VERSION 5.8 ;
BUSBITCHARS "[]" ;
DIVIDERCHAR "/" ;
 
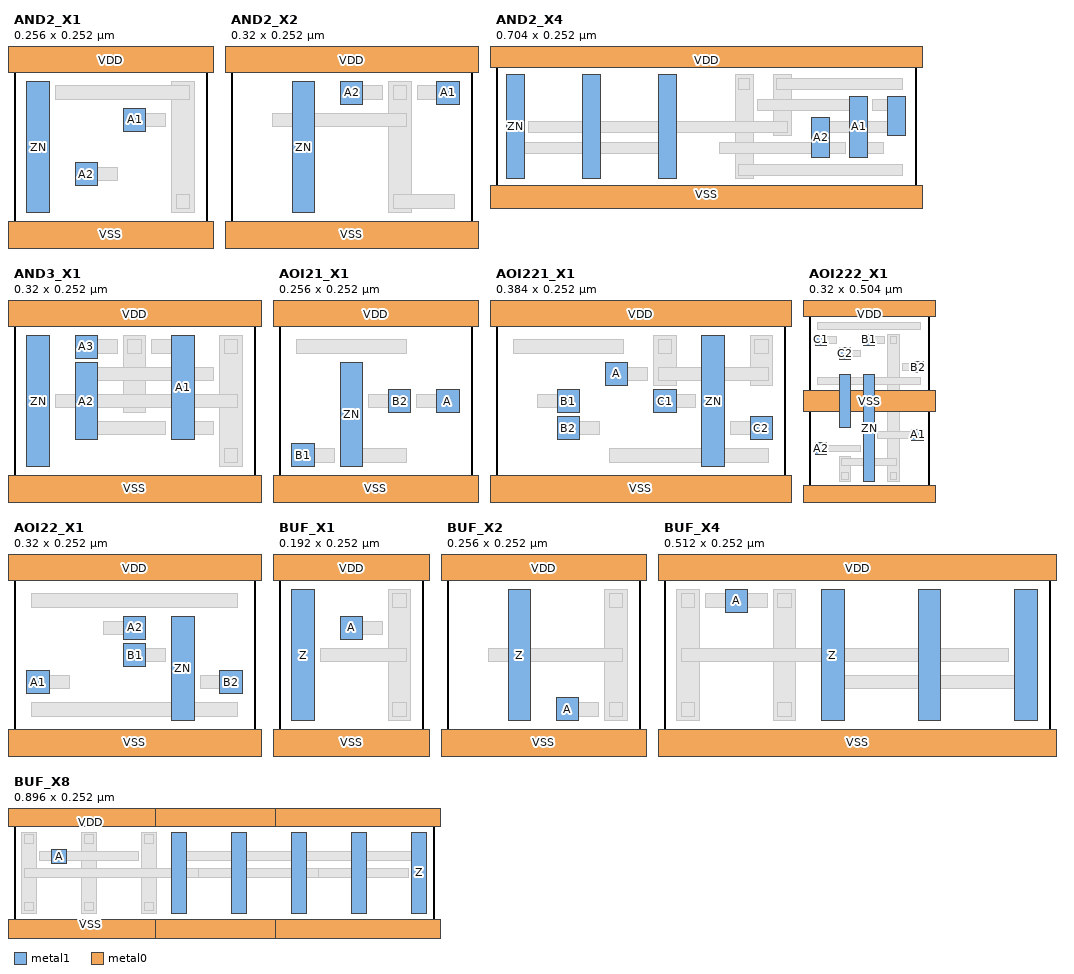
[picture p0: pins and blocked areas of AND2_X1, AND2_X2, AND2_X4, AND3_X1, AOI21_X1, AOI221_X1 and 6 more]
MACRO AND2_X1
  CLASS CORE ;
  FOREIGN AND2_X1 0 0 ;
  SIZE 0.256 BY 0.252 ;
  ORIGIN 0.0 0.0 ;
  SYMMETRY X Y ;
  PIN A1
    DIRECTION INPUT ;
    USE SIGNAL ;
    ANTENNAGATEAREA 0.001656 ;
    PORT
      LAYER metal1 ;
        RECT 0.145 0.147 0.175 0.177 ;
    END
  END A1
  PIN A2
    DIRECTION INPUT ;
    USE SIGNAL ;
    ANTENNAGATEAREA 0.001656 ;
    PORT
      LAYER metal1 ;
        RECT 0.081 0.075 0.111 0.105 ;
    END
  END A2
  PIN ZN
    DIRECTION OUTPUT ;
    USE SIGNAL ;
    ANTENNADIFFAREA 0.004232 ;
    PORT
      LAYER metal1 ;
        RECT 0.017 0.039 0.047 0.213 ;
    END
  END ZN
  PIN VDD
    DIRECTION INOUT ;
    USE POWER ;
    PORT
      LAYER metal0 ;
        RECT -0.019 0.225 0.275 0.279 ;
    END
  END VDD
  PIN VSS
    DIRECTION INOUT ;
    USE GROUND ;
    PORT
      LAYER metal0 ;
        RECT -0.019 -0.027 0.275 0.027 ;
    END
  END VSS
  OBS
    LAYER metal1 ;
      RECT 0.209 0.039 0.239 0.213 ;
    LAYER metal0 ;
      RECT 0.055 0.189 0.233 0.207 ;
      RECT 0.215 0.045 0.233 0.063 ;
      RECT 0.151 0.153 0.201 0.171 ;
      RECT 0.087 0.081 0.137 0.099 ;
      RECT 0.023 0.189 0.041 0.207 ;
      RECT 0.023 0.045 0.041 0.063 ;
  END
END AND2_X1

MACRO AND2_X2
  CLASS CORE ;
  FOREIGN AND2_X2 0 0 ;
  SIZE 0.32 BY 0.252 ;
  ORIGIN 0.0 0.0 ;
  SYMMETRY X Y ;
  PIN A1
    DIRECTION INPUT ;
    USE SIGNAL ;
    ANTENNAGATEAREA 0.001656 ;
    PORT
      LAYER metal1 ;
        RECT 0.273 0.183 0.303 0.213 ;
    END
  END A1
  PIN A2
    DIRECTION INPUT ;
    USE SIGNAL ;
    ANTENNAGATEAREA 0.001656 ;
    PORT
      LAYER metal1 ;
        RECT 0.145 0.183 0.175 0.213 ;
    END
  END A2
  PIN ZN
    DIRECTION OUTPUT ;
    USE SIGNAL ;
    ANTENNADIFFAREA 0.004232 ;
    PORT
      LAYER metal1 ;
        RECT 0.081 0.039 0.111 0.213 ;
    END
  END ZN
  PIN VDD
    DIRECTION INOUT ;
    USE POWER ;
    PORT
      LAYER metal0 ;
        RECT -0.019 0.225 0.339 0.279 ;
    END
  END VDD
  PIN VSS
    DIRECTION INOUT ;
    USE GROUND ;
    PORT
      LAYER metal0 ;
        RECT -0.019 -0.027 0.339 0.027 ;
    END
  END VSS
  OBS
    LAYER metal1 ;
      RECT 0.209 0.039 0.239 0.213 ;
    LAYER metal0 ;
      RECT 0.055 0.153 0.233 0.171 ;
      RECT 0.215 0.045 0.297 0.063 ;
      RECT 0.215 0.189 0.233 0.207 ;
      RECT 0.247 0.189 0.297 0.207 ;
      RECT 0.151 0.189 0.201 0.207 ;
      RECT 0.087 0.189 0.105 0.207 ;
      RECT 0.087 0.045 0.105 0.063 ;
  END
END AND2_X2

MACRO AND2_X4
  CLASS CORE ;
  FOREIGN AND2_X4 0 0 ;
  SIZE 0.704 BY 0.252 ;
  ORIGIN 0.0 0.0 ;
  SYMMETRY X Y ;
  PIN A1
    DIRECTION INPUT ;
    USE SIGNAL ;
    ANTENNAGATEAREA 0.003312 ;
    PORT
      LAYER metal1 ;
        RECT 0.593 0.075 0.623 0.177 ;
    END
  END A1
  PIN A2
    DIRECTION INPUT ;
    USE SIGNAL ;
    ANTENNAGATEAREA 0.003312 ;
    PORT
      LAYER metal1 ;
        RECT 0.529 0.075 0.559 0.141 ;
        RECT 0.657 0.111 0.687 0.177 ;
    END
  END A2
  PIN ZN
    DIRECTION OUTPUT ;
    USE SIGNAL ;
    ANTENNADIFFAREA 0.012696 ;
    PORT
      LAYER metal1 ;
        RECT 0.017 0.039 0.047 0.213 ;
        RECT 0.145 0.039 0.175 0.213 ;
        RECT 0.273 0.039 0.303 0.213 ;
    END
  END ZN
  PIN VDD
    DIRECTION INOUT ;
    USE POWER ;
    PORT
      LAYER metal0 ;
        RECT -0.019 0.225 0.723 0.279 ;
    END
  END VDD
  PIN VSS
    DIRECTION INOUT ;
    USE GROUND ;
    PORT
      LAYER metal0 ;
        RECT -0.019 -0.027 0.723 0.027 ;
    END
  END VSS
  OBS
    LAYER metal1 ;
      RECT 0.401 0.039 0.431 0.213 ;
      RECT 0.465 0.111 0.495 0.213 ;
    LAYER metal0 ;
      RECT 0.471 0.189 0.681 0.207 ;
      RECT 0.055 0.117 0.489 0.135 ;
      RECT 0.407 0.045 0.681 0.063 ;
      RECT 0.407 0.189 0.425 0.207 ;
      RECT 0.439 0.153 0.617 0.171 ;
      RECT 0.599 0.081 0.649 0.099 ;
      RECT 0.535 0.117 0.681 0.135 ;
      RECT 0.375 0.081 0.585 0.099 ;
      RECT 0.631 0.153 0.681 0.171 ;
      RECT 0.023 0.081 0.297 0.099 ;
      RECT 0.023 0.189 0.041 0.207 ;
      RECT 0.023 0.045 0.041 0.063 ;
      RECT 0.279 0.045 0.297 0.063 ;
      RECT 0.279 0.189 0.297 0.207 ;
      RECT 0.151 0.189 0.169 0.207 ;
      RECT 0.151 0.045 0.169 0.063 ;
  END
END AND2_X4

MACRO AND3_X1
  CLASS CORE ;
  FOREIGN AND3_X1 0 0 ;
  SIZE 0.32 BY 0.252 ;
  ORIGIN 0.0 0.0 ;
  SYMMETRY X Y ;
  PIN A1
    DIRECTION INPUT ;
    USE SIGNAL ;
    ANTENNAGATEAREA 0.001656 ;
    PORT
      LAYER metal1 ;
        RECT 0.209 0.075 0.239 0.213 ;
    END
  END A1
  PIN A2
    DIRECTION INPUT ;
    USE SIGNAL ;
    ANTENNAGATEAREA 0.001656 ;
    PORT
      LAYER metal1 ;
        RECT 0.081 0.075 0.111 0.177 ;
    END
  END A2
  PIN A3
    DIRECTION INPUT ;
    USE SIGNAL ;
    ANTENNAGATEAREA 0.001656 ;
    PORT
      LAYER metal1 ;
        RECT 0.081 0.183 0.111 0.213 ;
    END
  END A3
  PIN ZN
    DIRECTION OUTPUT ;
    USE SIGNAL ;
    ANTENNADIFFAREA 0.004232 ;
    PORT
      LAYER metal1 ;
        RECT 0.017 0.039 0.047 0.213 ;
    END
  END ZN
  PIN VDD
    DIRECTION INOUT ;
    USE POWER ;
    PORT
      LAYER metal0 ;
        RECT -0.019 0.225 0.339 0.279 ;
    END
  END VDD
  PIN VSS
    DIRECTION INOUT ;
    USE GROUND ;
    PORT
      LAYER metal0 ;
        RECT -0.019 -0.027 0.339 0.027 ;
    END
  END VSS
  OBS
    LAYER metal1 ;
      RECT 0.145 0.111 0.175 0.213 ;
      RECT 0.273 0.039 0.303 0.213 ;
    LAYER metal0 ;
      RECT 0.055 0.117 0.297 0.135 ;
      RECT 0.151 0.189 0.169 0.207 ;
      RECT 0.279 0.189 0.297 0.207 ;
      RECT 0.279 0.045 0.297 0.063 ;
      RECT 0.215 0.081 0.265 0.099 ;
      RECT 0.183 0.189 0.233 0.207 ;
      RECT 0.087 0.153 0.265 0.171 ;
      RECT 0.087 0.081 0.201 0.099 ;
      RECT 0.087 0.189 0.137 0.207 ;
      RECT 0.023 0.189 0.041 0.207 ;
      RECT 0.023 0.045 0.041 0.063 ;
  END
END AND3_X1

MACRO AOI21_X1
  CLASS CORE ;
  FOREIGN AOI21_X1 0 0 ;
  SIZE 0.256 BY 0.252 ;
  ORIGIN 0.0 0.0 ;
  SYMMETRY X Y ;
  PIN A
    DIRECTION INPUT ;
    USE SIGNAL ;
    ANTENNAGATEAREA 0.001656 ;
    PORT
      LAYER metal1 ;
        RECT 0.209 0.111 0.239 0.141 ;
    END
  END A
  PIN B1
    DIRECTION INPUT ;
    USE SIGNAL ;
    ANTENNAGATEAREA 0.001656 ;
    PORT
      LAYER metal1 ;
        RECT 0.017 0.039 0.047 0.069 ;
    END
  END B1
  PIN B2
    DIRECTION INPUT ;
    USE SIGNAL ;
    ANTENNAGATEAREA 0.001656 ;
    PORT
      LAYER metal1 ;
        RECT 0.145 0.111 0.175 0.141 ;
    END
  END B2
  PIN ZN
    DIRECTION OUTPUT ;
    USE SIGNAL ;
    ANTENNADIFFAREA 0.004232 ;
    PORT
      LAYER metal1 ;
        RECT 0.081 0.039 0.111 0.177 ;
    END
  END ZN
  PIN VDD
    DIRECTION INOUT ;
    USE POWER ;
    PORT
      LAYER metal0 ;
        RECT -0.019 0.225 0.275 0.279 ;
    END
  END VDD
  PIN VSS
    DIRECTION INOUT ;
    USE GROUND ;
    PORT
      LAYER metal0 ;
        RECT -0.019 -0.027 0.275 0.027 ;
    END
  END VSS
  OBS
    LAYER metal0 ;
      RECT 0.023 0.189 0.169 0.207 ;
      RECT 0.183 0.117 0.233 0.135 ;
      RECT 0.023 0.045 0.073 0.063 ;
      RECT 0.119 0.117 0.169 0.135 ;
      RECT 0.087 0.045 0.169 0.063 ;
      RECT 0.087 0.153 0.105 0.171 ;
  END
END AOI21_X1

MACRO AOI221_X1
  CLASS CORE ;
  FOREIGN AOI221_X1 0 0 ;
  SIZE 0.384 BY 0.252 ;
  ORIGIN 0.0 0.0 ;
  SYMMETRY X Y ;
  PIN A
    DIRECTION INPUT ;
    USE SIGNAL ;
    ANTENNAGATEAREA 0.001656 ;
    PORT
      LAYER metal1 ;
        RECT 0.145 0.147 0.175 0.177 ;
    END
  END A
  PIN B1
    DIRECTION INPUT ;
    USE SIGNAL ;
    ANTENNAGATEAREA 0.001656 ;
    PORT
      LAYER metal1 ;
        RECT 0.081 0.111 0.111 0.141 ;
    END
  END B1
  PIN B2
    DIRECTION INPUT ;
    USE SIGNAL ;
    ANTENNAGATEAREA 0.001656 ;
    PORT
      LAYER metal1 ;
        RECT 0.081 0.075 0.111 0.105 ;
    END
  END B2
  PIN C1
    DIRECTION INPUT ;
    USE SIGNAL ;
    ANTENNAGATEAREA 0.001656 ;
    PORT
      LAYER metal1 ;
        RECT 0.209 0.111 0.239 0.141 ;
    END
  END C1
  PIN C2
    DIRECTION INPUT ;
    USE SIGNAL ;
    ANTENNAGATEAREA 0.001656 ;
    PORT
      LAYER metal1 ;
        RECT 0.337 0.075 0.367 0.105 ;
    END
  END C2
  PIN ZN
    DIRECTION OUTPUT ;
    USE SIGNAL ;
    ANTENNADIFFAREA 0.006348 ;
    PORT
      LAYER metal1 ;
        RECT 0.273 0.039 0.303 0.213 ;
    END
  END ZN
  PIN VDD
    DIRECTION INOUT ;
    USE POWER ;
    PORT
      LAYER metal0 ;
        RECT -0.019 0.225 0.403 0.279 ;
    END
  END VDD
  PIN VSS
    DIRECTION INOUT ;
    USE GROUND ;
    PORT
      LAYER metal0 ;
        RECT -0.019 -0.027 0.403 0.027 ;
    END
  END VSS
  OBS
    LAYER metal1 ;
      RECT 0.209 0.147 0.239 0.213 ;
      RECT 0.337 0.147 0.367 0.213 ;
    LAYER metal0 ;
      RECT 0.023 0.189 0.169 0.207 ;
      RECT 0.215 0.153 0.361 0.171 ;
      RECT 0.215 0.189 0.233 0.207 ;
      RECT 0.343 0.189 0.361 0.207 ;
      RECT 0.151 0.153 0.201 0.171 ;
      RECT 0.055 0.117 0.105 0.135 ;
      RECT 0.087 0.081 0.137 0.099 ;
      RECT 0.215 0.117 0.265 0.135 ;
      RECT 0.311 0.081 0.361 0.099 ;
      RECT 0.279 0.189 0.297 0.207 ;
      RECT 0.151 0.045 0.361 0.063 ;
  END
END AOI221_X1

MACRO AOI222_X1
  CLASS CORE ;
  FOREIGN AOI222_X1 0 0 ;
  SIZE 0.32 BY 0.504 ;
  ORIGIN 0.0 0.0 ;
  SYMMETRY X Y ;
  PIN A1
    DIRECTION INPUT ;
    USE SIGNAL ;
    ANTENNAGATEAREA 0.001656 ;
    PORT
      LAYER metal1 ;
        RECT 0.273 0.147 0.303 0.177 ;
    END
  END A1
  PIN A2
    DIRECTION INPUT ;
    USE SIGNAL ;
    ANTENNAGATEAREA 0.001656 ;
    PORT
      LAYER metal1 ;
        RECT 0.017 0.111 0.047 0.141 ;
    END
  END A2
  PIN B1
    DIRECTION INPUT ;
    USE SIGNAL ;
    ANTENNAGATEAREA 0.001656 ;
    PORT
      LAYER metal1 ;
        RECT 0.145 0.399 0.175 0.429 ;
    END
  END B1
  PIN B2
    DIRECTION INPUT ;
    USE SIGNAL ;
    ANTENNAGATEAREA 0.001656 ;
    PORT
      LAYER metal1 ;
        RECT 0.273 0.327 0.303 0.357 ;
    END
  END B2
  PIN C1
    DIRECTION INPUT ;
    USE SIGNAL ;
    ANTENNAGATEAREA 0.001656 ;
    PORT
      LAYER metal1 ;
        RECT 0.017 0.399 0.047 0.429 ;
    END
  END C1
  PIN C2
    DIRECTION INPUT ;
    USE SIGNAL ;
    ANTENNAGATEAREA 0.001656 ;
    PORT
      LAYER metal1 ;
        RECT 0.081 0.363 0.111 0.393 ;
    END
  END C2
  PIN ZN
    DIRECTION OUTPUT ;
    USE SIGNAL ;
    ANTENNADIFFAREA 0.008464 ;
    PORT
      LAYER metal1 ;
        RECT 0.081 0.183 0.111 0.321 ;
        RECT 0.145 0.039 0.175 0.321 ;
    END
  END ZN
  PIN VDD
    DIRECTION INOUT ;
    USE POWER ;
    PORT
      LAYER metal0 ;
        RECT -0.019 -0.027 0.339 0.027 ;
        RECT -0.019 0.477 0.339 0.531 ;
    END
  END VDD
  PIN VSS
    DIRECTION INOUT ;
    USE GROUND ;
    PORT
      LAYER metal0 ;
        RECT -0.019 0.225 0.339 0.279 ;
    END
  END VSS
  OBS
    LAYER metal1 ;
      RECT 0.209 0.039 0.239 0.429 ;
      RECT 0.081 0.039 0.111 0.105 ;
    LAYER metal0 ;
      RECT 0.215 0.045 0.233 0.063 ;
      RECT 0.087 0.045 0.105 0.063 ;
      RECT 0.215 0.405 0.233 0.423 ;
      RECT 0.087 0.081 0.233 0.099 ;
      RECT 0.023 0.441 0.297 0.459 ;
      RECT 0.183 0.153 0.297 0.171 ;
      RECT 0.023 0.117 0.137 0.135 ;
      RECT 0.151 0.405 0.201 0.423 ;
      RECT 0.247 0.333 0.297 0.351 ;
      RECT 0.023 0.405 0.073 0.423 ;
      RECT 0.087 0.369 0.137 0.387 ;
      RECT 0.087 0.189 0.105 0.207 ;
      RECT 0.023 0.297 0.297 0.315 ;
      RECT 0.151 0.045 0.169 0.063 ;
  END
END AOI222_X1

MACRO AOI22_X1
  CLASS CORE ;
  FOREIGN AOI22_X1 0 0 ;
  SIZE 0.32 BY 0.252 ;
  ORIGIN 0.0 0.0 ;
  SYMMETRY X Y ;
  PIN A1
    DIRECTION INPUT ;
    USE SIGNAL ;
    ANTENNAGATEAREA 0.001656 ;
    PORT
      LAYER metal1 ;
        RECT 0.017 0.075 0.047 0.105 ;
    END
  END A1
  PIN A2
    DIRECTION INPUT ;
    USE SIGNAL ;
    ANTENNAGATEAREA 0.001656 ;
    PORT
      LAYER metal1 ;
        RECT 0.145 0.147 0.175 0.177 ;
    END
  END A2
  PIN B1
    DIRECTION INPUT ;
    USE SIGNAL ;
    ANTENNAGATEAREA 0.001656 ;
    PORT
      LAYER metal1 ;
        RECT 0.145 0.111 0.175 0.141 ;
    END
  END B1
  PIN B2
    DIRECTION INPUT ;
    USE SIGNAL ;
    ANTENNAGATEAREA 0.001656 ;
    PORT
      LAYER metal1 ;
        RECT 0.273 0.075 0.303 0.105 ;
    END
  END B2
  PIN ZN
    DIRECTION OUTPUT ;
    USE SIGNAL ;
    ANTENNADIFFAREA 0.006348 ;
    PORT
      LAYER metal1 ;
        RECT 0.209 0.039 0.239 0.177 ;
    END
  END ZN
  PIN VDD
    DIRECTION INOUT ;
    USE POWER ;
    PORT
      LAYER metal0 ;
        RECT -0.019 0.225 0.339 0.279 ;
    END
  END VDD
  PIN VSS
    DIRECTION INOUT ;
    USE GROUND ;
    PORT
      LAYER metal0 ;
        RECT -0.019 -0.027 0.339 0.027 ;
    END
  END VSS
  OBS
    LAYER metal0 ;
      RECT 0.023 0.189 0.297 0.207 ;
      RECT 0.023 0.081 0.073 0.099 ;
      RECT 0.119 0.153 0.169 0.171 ;
      RECT 0.151 0.117 0.201 0.135 ;
      RECT 0.247 0.081 0.297 0.099 ;
      RECT 0.215 0.153 0.233 0.171 ;
      RECT 0.023 0.045 0.297 0.063 ;
  END
END AOI22_X1

MACRO BUF_X1
  CLASS CORE ;
  FOREIGN BUF_X1 0 0 ;
  SIZE 0.192 BY 0.252 ;
  ORIGIN 0.0 0.0 ;
  SYMMETRY X Y ;
  PIN A
    DIRECTION INPUT ;
    USE SIGNAL ;
    ANTENNAGATEAREA 0.001656 ;
    PORT
      LAYER metal1 ;
        RECT 0.081 0.147 0.111 0.177 ;
    END
  END A
  PIN Z
    DIRECTION OUTPUT ;
    USE SIGNAL ;
    ANTENNADIFFAREA 0.004232 ;
    PORT
      LAYER metal1 ;
        RECT 0.017 0.039 0.047 0.213 ;
    END
  END Z
  PIN VDD
    DIRECTION INOUT ;
    USE POWER ;
    PORT
      LAYER metal0 ;
        RECT -0.019 0.225 0.211 0.279 ;
    END
  END VDD
  PIN VSS
    DIRECTION INOUT ;
    USE GROUND ;
    PORT
      LAYER metal0 ;
        RECT -0.019 -0.027 0.211 0.027 ;
    END
  END VSS
  OBS
    LAYER metal1 ;
      RECT 0.145 0.039 0.175 0.213 ;
    LAYER metal0 ;
      RECT 0.055 0.117 0.169 0.135 ;
      RECT 0.151 0.189 0.169 0.207 ;
      RECT 0.151 0.045 0.169 0.063 ;
      RECT 0.087 0.153 0.137 0.171 ;
      RECT 0.023 0.189 0.041 0.207 ;
      RECT 0.023 0.045 0.041 0.063 ;
  END
END BUF_X1

MACRO BUF_X2
  CLASS CORE ;
  FOREIGN BUF_X2 0 0 ;
  SIZE 0.256 BY 0.252 ;
  ORIGIN 0.0 0.0 ;
  SYMMETRY X Y ;
  PIN A
    DIRECTION INPUT ;
    USE SIGNAL ;
    ANTENNAGATEAREA 0.001656 ;
    PORT
      LAYER metal1 ;
        RECT 0.145 0.039 0.175 0.069 ;
    END
  END A
  PIN Z
    DIRECTION OUTPUT ;
    USE SIGNAL ;
    ANTENNADIFFAREA 0.004232 ;
    PORT
      LAYER metal1 ;
        RECT 0.081 0.039 0.111 0.213 ;
    END
  END Z
  PIN VDD
    DIRECTION INOUT ;
    USE POWER ;
    PORT
      LAYER metal0 ;
        RECT -0.019 0.225 0.275 0.279 ;
    END
  END VDD
  PIN VSS
    DIRECTION INOUT ;
    USE GROUND ;
    PORT
      LAYER metal0 ;
        RECT -0.019 -0.027 0.275 0.027 ;
    END
  END VSS
  OBS
    LAYER metal1 ;
      RECT 0.209 0.039 0.239 0.213 ;
    LAYER metal0 ;
      RECT 0.055 0.117 0.233 0.135 ;
      RECT 0.215 0.189 0.233 0.207 ;
      RECT 0.215 0.045 0.233 0.063 ;
      RECT 0.151 0.045 0.201 0.063 ;
      RECT 0.087 0.189 0.105 0.207 ;
      RECT 0.087 0.045 0.105 0.063 ;
  END
END BUF_X2

MACRO BUF_X4
  CLASS CORE ;
  FOREIGN BUF_X4 0 0 ;
  SIZE 0.512 BY 0.252 ;
  ORIGIN 0.0 0.0 ;
  SYMMETRY X Y ;
  PIN A
    DIRECTION INPUT ;
    USE SIGNAL ;
    ANTENNAGATEAREA 0.003312 ;
    PORT
      LAYER metal1 ;
        RECT 0.081 0.183 0.111 0.213 ;
    END
  END A
  PIN Z
    DIRECTION OUTPUT ;
    USE SIGNAL ;
    ANTENNADIFFAREA 0.012696 ;
    PORT
      LAYER metal1 ;
        RECT 0.209 0.039 0.239 0.213 ;
        RECT 0.465 0.039 0.495 0.213 ;
        RECT 0.337 0.039 0.367 0.213 ;
    END
  END Z
  PIN VDD
    DIRECTION INOUT ;
    USE POWER ;
    PORT
      LAYER metal0 ;
        RECT -0.019 0.225 0.531 0.279 ;
    END
  END VDD
  PIN VSS
    DIRECTION INOUT ;
    USE GROUND ;
    PORT
      LAYER metal0 ;
        RECT -0.019 -0.027 0.531 0.027 ;
    END
  END VSS
  OBS
    LAYER metal1 ;
      RECT 0.017 0.039 0.047 0.213 ;
      RECT 0.145 0.039 0.175 0.213 ;
    LAYER metal0 ;
      RECT 0.023 0.117 0.457 0.135 ;
      RECT 0.023 0.189 0.041 0.207 ;
      RECT 0.151 0.189 0.169 0.207 ;
      RECT 0.023 0.045 0.041 0.063 ;
      RECT 0.151 0.045 0.169 0.063 ;
      RECT 0.055 0.189 0.137 0.207 ;
      RECT 0.215 0.045 0.233 0.063 ;
      RECT 0.215 0.189 0.233 0.207 ;
      RECT 0.215 0.081 0.489 0.099 ;
      RECT 0.343 0.045 0.361 0.063 ;
      RECT 0.343 0.189 0.361 0.207 ;
      RECT 0.471 0.045 0.489 0.063 ;
      RECT 0.471 0.189 0.489 0.207 ;
  END
END BUF_X4

MACRO BUF_X8
  CLASS CORE ;
  FOREIGN BUF_X8 0 0 ;
  SIZE 0.896 BY 0.252 ;
  ORIGIN 0.0 0.0 ;
  SYMMETRY X Y ;
  PIN A
    DIRECTION INPUT ;
    USE SIGNAL ;
    ANTENNAGATEAREA 0.006624 ;
    PORT
      LAYER metal1 ;
        RECT 0.081 0.147 0.111 0.177 ;
    END
  END A
  PIN Z
    DIRECTION OUTPUT ;
    USE SIGNAL ;
    ANTENNADIFFAREA 0.021160 ;
    PORT
      LAYER metal1 ;
        RECT 0.849 0.039 0.879 0.213 ;
        RECT 0.465 0.039 0.495 0.213 ;
        RECT 0.721 0.039 0.751 0.213 ;
        RECT 0.337 0.039 0.367 0.213 ;
        RECT 0.593 0.039 0.623 0.213 ;
    END
  END Z
  PIN VDD
    DIRECTION INOUT ;
    USE POWER ;
    PORT
      LAYER metal0 ;
        RECT -0.019 0.225 0.339 0.279 ;
        RECT 0.301 0.225 0.659 0.279 ;
        RECT 0.557 0.225 0.915 0.279 ;
    END
  END VDD
  PIN VSS
    DIRECTION INOUT ;
    USE GROUND ;
    PORT
      LAYER metal0 ;
        RECT 0.557 -0.027 0.915 0.027 ;
        RECT -0.019 -0.027 0.339 0.027 ;
        RECT 0.301 -0.027 0.659 0.027 ;
    END
  END VSS
  OBS
    LAYER metal1 ;
      RECT 0.273 0.039 0.303 0.213 ;
      RECT 0.145 0.039 0.175 0.213 ;
      RECT 0.017 0.039 0.047 0.213 ;
    LAYER metal0 ;
      RECT 0.631 0.117 0.841 0.135 ;
      RECT 0.375 0.117 0.649 0.135 ;
      RECT 0.279 0.045 0.297 0.063 ;
      RECT 0.151 0.045 0.169 0.063 ;
      RECT 0.023 0.045 0.041 0.063 ;
      RECT 0.279 0.189 0.297 0.207 ;
      RECT 0.151 0.189 0.169 0.207 ;
      RECT 0.023 0.189 0.041 0.207 ;
      RECT 0.023 0.117 0.393 0.135 ;
      RECT 0.055 0.153 0.265 0.171 ;
      RECT 0.855 0.189 0.873 0.207 ;
      RECT 0.599 0.153 0.873 0.171 ;
      RECT 0.343 0.153 0.617 0.171 ;
      RECT 0.855 0.045 0.873 0.063 ;
      RECT 0.343 0.045 0.361 0.063 ;
      RECT 0.471 0.045 0.489 0.063 ;
      RECT 0.471 0.189 0.489 0.207 ;
      RECT 0.599 0.045 0.617 0.063 ;
      RECT 0.727 0.045 0.745 0.063 ;
      RECT 0.727 0.189 0.745 0.207 ;
      RECT 0.343 0.189 0.361 0.207 ;
      RECT 0.599 0.189 0.617 0.207 ;
  END
END BUF_X8

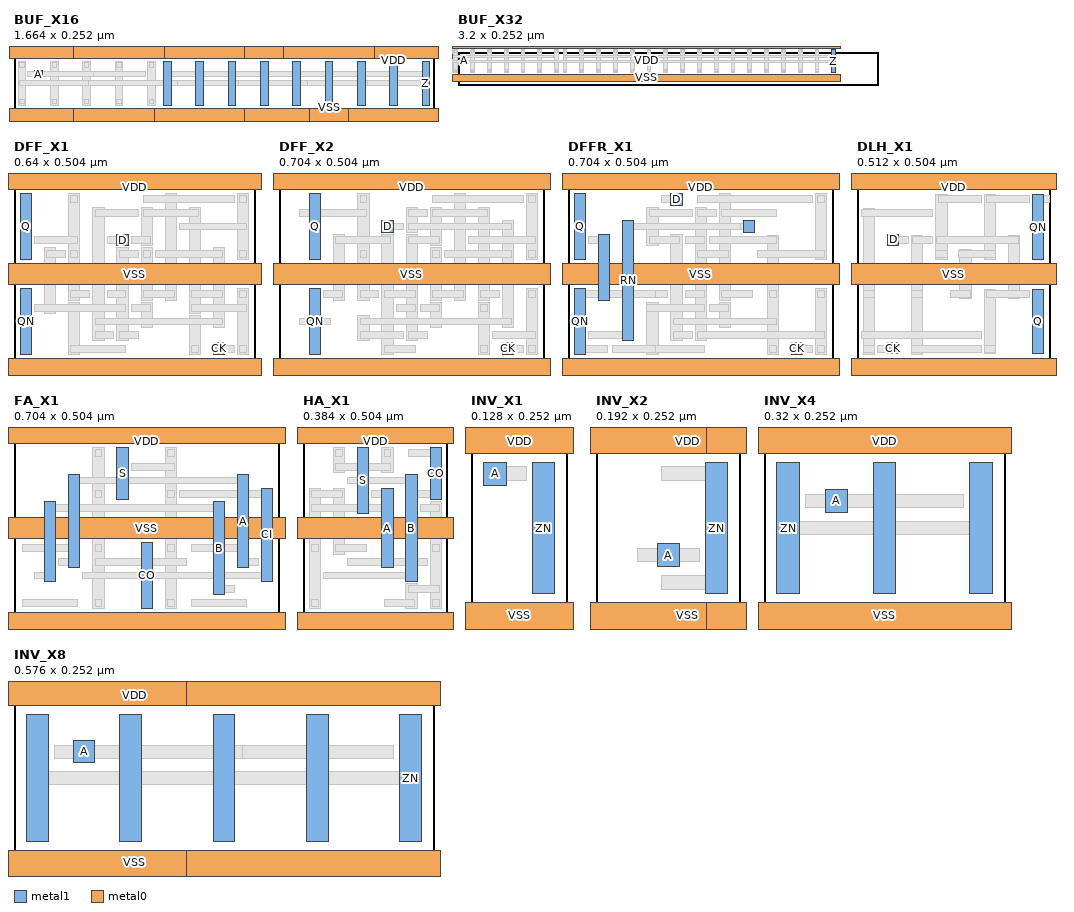
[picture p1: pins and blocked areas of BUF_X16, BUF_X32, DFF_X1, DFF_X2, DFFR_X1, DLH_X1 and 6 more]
MACRO BUF_X16
  CLASS CORE ;
  FOREIGN BUF_X16 0 0 ;
  SIZE 1.664 BY 0.252 ;
  ORIGIN 0.0 0.0 ;
  SYMMETRY X Y ;
  PIN A
    DIRECTION INPUT ;
    USE SIGNAL ;
    ANTENNAGATEAREA 0.013248 ;
    PORT
      LAYER metal1 ;
        RECT 0.081 0.147 0.111 0.177 ;
    END
  END A
  PIN Z
    DIRECTION OUTPUT ;
    USE SIGNAL ;
    ANTENNADIFFAREA 0.038088 ;
    PORT
      LAYER metal1 ;
        RECT 1.617 0.039 1.647 0.213 ;
        RECT 1.233 0.039 1.263 0.213 ;
        RECT 0.721 0.039 0.751 0.213 ;
        RECT 0.849 0.039 0.879 0.213 ;
        RECT 1.489 0.039 1.519 0.213 ;
        RECT 1.361 0.039 1.391 0.213 ;
        RECT 0.593 0.039 0.623 0.213 ;
        RECT 1.105 0.039 1.135 0.213 ;
        RECT 0.977 0.039 1.007 0.213 ;
    END
  END Z
  PIN VDD
    DIRECTION INOUT ;
    USE POWER ;
    PORT
      LAYER metal0 ;
        RECT -0.019 0.225 0.339 0.279 ;
        RECT 0.557 0.225 0.915 0.279 ;
        RECT 1.325 0.225 1.683 0.279 ;
        RECT 0.813 0.225 1.171 0.279 ;
        RECT 0.237 0.225 0.595 0.279 ;
        RECT 1.069 0.225 1.427 0.279 ;
    END
  END VDD
  PIN VSS
    DIRECTION INOUT ;
    USE GROUND ;
    PORT
      LAYER metal0 ;
        RECT 1.069 -0.027 1.427 0.027 ;
        RECT 0.813 -0.027 1.171 0.027 ;
        RECT 0.237 -0.027 0.595 0.027 ;
        RECT 0.557 -0.027 0.915 0.027 ;
        RECT -0.019 -0.027 0.339 0.027 ;
        RECT 1.325 -0.027 1.683 0.027 ;
    END
  END VSS
  OBS
    LAYER metal1 ;
      RECT 0.529 0.039 0.559 0.213 ;
      RECT 0.401 0.039 0.431 0.213 ;
      RECT 0.273 0.039 0.303 0.213 ;
      RECT 0.145 0.039 0.175 0.213 ;
      RECT 0.017 0.039 0.047 0.213 ;
    LAYER metal0 ;
      RECT 1.143 0.117 1.401 0.135 ;
      RECT 1.399 0.117 1.609 0.135 ;
      RECT 0.887 0.117 1.161 0.135 ;
      RECT 0.631 0.117 0.889 0.135 ;
      RECT 0.535 0.045 0.553 0.063 ;
      RECT 0.407 0.045 0.425 0.063 ;
      RECT 0.279 0.045 0.297 0.063 ;
      RECT 0.535 0.189 0.553 0.207 ;
      RECT 0.407 0.189 0.425 0.207 ;
      RECT 0.279 0.189 0.297 0.207 ;
      RECT 0.279 0.117 0.649 0.135 ;
      RECT 0.151 0.045 0.169 0.063 ;
      RECT 0.023 0.045 0.041 0.063 ;
      RECT 0.151 0.189 0.169 0.207 ;
      RECT 0.023 0.189 0.041 0.207 ;
      RECT 0.023 0.117 0.297 0.135 ;
      RECT 0.311 0.153 0.521 0.171 ;
      RECT 0.055 0.153 0.313 0.171 ;
      RECT 0.599 0.153 0.873 0.171 ;
      RECT 1.367 0.153 1.641 0.171 ;
      RECT 1.623 0.189 1.641 0.207 ;
      RECT 1.111 0.153 1.385 0.171 ;
      RECT 0.855 0.153 1.129 0.171 ;
      RECT 1.623 0.045 1.641 0.063 ;
      RECT 1.367 0.045 1.385 0.063 ;
      RECT 1.239 0.189 1.257 0.207 ;
      RECT 0.599 0.045 0.617 0.063 ;
      RECT 1.367 0.189 1.385 0.207 ;
      RECT 0.983 0.045 1.001 0.063 ;
      RECT 1.495 0.045 1.513 0.063 ;
      RECT 0.983 0.189 1.001 0.207 ;
      RECT 0.727 0.045 0.745 0.063 ;
      RECT 1.111 0.189 1.129 0.207 ;
      RECT 0.727 0.189 0.745 0.207 ;
      RECT 1.495 0.189 1.513 0.207 ;
      RECT 1.239 0.045 1.257 0.063 ;
      RECT 1.111 0.045 1.129 0.063 ;
      RECT 0.855 0.189 0.873 0.207 ;
      RECT 0.599 0.189 0.617 0.207 ;
      RECT 0.855 0.045 0.873 0.063 ;
  END
END BUF_X16

MACRO BUF_X32
  CLASS CORE ;
  ORIGIN 0 0 ;
  FOREIGN BUF_X32 0 0 ;
  SIZE 3.2 BY 0.252 ;
  PIN VDD
    DIRECTION INOUT ;
    USE POWER ;
    PORT
      LAYER metal0 ;
        RECT -0.324 0.28 2.914 0.334 ;
    END
  END VDD
  PIN VSS
    DIRECTION INOUT ;
    USE GROUND ;
    PORT
      LAYER metal0 ;
        RECT -0.324 0.028 2.914 0.082 ;
    END
  END VSS
  PIN A
    DIRECTION INPUT ;
    USE SIGNAL ;
    PORT
      LAYER metal1 ;
        RECT -0.224 0.202 -0.194 0.232 ;
    END
  END A
  PIN Z
    DIRECTION OUTPUT ;
    USE SIGNAL ;
    PORT
      LAYER metal1 ;
        RECT 2.848 0.094 2.878 0.268 ;
    END
  END Z
  OBS
    LAYER metal1 ;
      RECT -0.288 0.094 -0.258 0.268 ;
      RECT -0.16 0.094 -0.13 0.268 ;
      RECT -0.032 0.094 -0.002 0.268 ;
      RECT 0.096 0.094 0.126 0.268 ;
      RECT 0.224 0.094 0.254 0.268 ;
      RECT 0.352 0.094 0.382 0.268 ;
      RECT 0.48 0.094 0.51 0.268 ;
      RECT 0.608 0.094 0.638 0.268 ;
      RECT 0.736 0.094 0.766 0.268 ;
      RECT 0.8 0.094 0.83 0.268 ;
      RECT 0.928 0.094 0.958 0.268 ;
      RECT 1.056 0.094 1.086 0.268 ;
      RECT 1.184 0.094 1.214 0.268 ;
      RECT 1.312 0.094 1.342 0.268 ;
      RECT 1.44 0.094 1.47 0.268 ;
      RECT 1.568 0.094 1.598 0.268 ;
      RECT 1.696 0.094 1.726 0.268 ;
      RECT 1.824 0.094 1.854 0.268 ;
      RECT 1.952 0.094 1.982 0.268 ;
      RECT 2.08 0.094 2.11 0.268 ;
      RECT 2.208 0.094 2.238 0.268 ;
      RECT 2.336 0.094 2.366 0.268 ;
      RECT 2.464 0.094 2.494 0.268 ;
      RECT 2.592 0.094 2.622 0.268 ;
      RECT 2.72 0.094 2.75 0.268 ;
    LAYER metal0 ;
      RECT -0.282 0.1 -0.264 0.118 ;
      RECT -0.154 0.1 -0.136 0.118 ;
      RECT -0.026 0.1 -0.008 0.118 ;
      RECT 0.102 0.1 0.12 0.118 ;
      RECT 0.23 0.1 0.248 0.118 ;
      RECT 0.358 0.1 0.376 0.118 ;
      RECT 0.486 0.1 0.504 0.118 ;
      RECT 0.614 0.1 0.632 0.118 ;
      RECT 0.742 0.1 0.76 0.118 ;
      RECT 0.806 0.1 0.824 0.118 ;
      RECT 0.934 0.1 0.952 0.118 ;
      RECT 1.062 0.1 1.08 0.118 ;
      RECT 1.19 0.1 1.208 0.118 ;
      RECT 1.318 0.1 1.336 0.118 ;
      RECT 1.446 0.1 1.464 0.118 ;
      RECT 1.574 0.1 1.592 0.118 ;
      RECT 1.702 0.1 1.72 0.118 ;
      RECT 1.83 0.1 1.848 0.118 ;
      RECT 1.958 0.1 1.976 0.118 ;
      RECT 2.086 0.1 2.104 0.118 ;
      RECT 2.214 0.1 2.232 0.118 ;
      RECT 2.342 0.1 2.36 0.118 ;
      RECT 2.47 0.1 2.488 0.118 ;
      RECT 2.598 0.1 2.616 0.118 ;
      RECT 2.726 0.1 2.744 0.118 ;
      RECT 2.854 0.1 2.872 0.118 ;
      RECT -0.282 0.172 2.84 0.19 ;
      RECT -0.25 0.208 0.728 0.226 ;
      RECT 0.806 0.208 2.872 0.226 ;
      RECT -0.282 0.244 -0.264 0.262 ;
      RECT -0.154 0.244 -0.136 0.262 ;
      RECT -0.026 0.244 -0.008 0.262 ;
      RECT 0.102 0.244 0.12 0.262 ;
      RECT 0.23 0.244 0.248 0.262 ;
      RECT 0.358 0.244 0.376 0.262 ;
      RECT 0.486 0.244 0.504 0.262 ;
      RECT 0.614 0.244 0.632 0.262 ;
      RECT 0.742 0.244 0.76 0.262 ;
      RECT 0.806 0.244 0.824 0.262 ;
      RECT 0.934 0.244 0.952 0.262 ;
      RECT 1.062 0.244 1.08 0.262 ;
      RECT 1.19 0.244 1.208 0.262 ;
      RECT 1.318 0.244 1.336 0.262 ;
      RECT 1.446 0.244 1.464 0.262 ;
      RECT 1.574 0.244 1.592 0.262 ;
      RECT 1.702 0.244 1.72 0.262 ;
      RECT 1.83 0.244 1.848 0.262 ;
      RECT 1.958 0.244 1.976 0.262 ;
      RECT 2.086 0.244 2.104 0.262 ;
      RECT 2.214 0.244 2.232 0.262 ;
      RECT 2.342 0.244 2.36 0.262 ;
      RECT 2.47 0.244 2.488 0.262 ;
      RECT 2.598 0.244 2.616 0.262 ;
      RECT 2.726 0.244 2.744 0.262 ;
      RECT 2.854 0.244 2.872 0.262 ;
  END
END BUF_X32


MACRO DFF_X1
  CLASS CORE ;
  FOREIGN DFF_X1 0 0 ;
  SIZE 0.64 BY 0.504 ;
  ORIGIN 0.0 0.0 ;
  SYMMETRY X Y ;
  PIN CK
    DIRECTION INPUT ;
    USE CLOCK ;
    ANTENNAGATEAREA 0.001656 ;
    PORT
      LAYER metal1 ;
        RECT 0.529 0.039 0.559 0.069 ;
    END
  END CK
  PIN D
    DIRECTION INPUT ;
    USE SIGNAL ;
    ANTENNAGATEAREA 0.001656 ;
    PORT
      LAYER metal1 ;
        RECT 0.273 0.327 0.303 0.357 ;
    END
  END D
  PIN Q
    DIRECTION OUTPUT ;
    USE SIGNAL ;
    ANTENNADIFFAREA 0.004232 ;
    PORT
      LAYER metal1 ;
        RECT 0.017 0.291 0.047 0.465 ;
    END
  END Q
  PIN QN
    DIRECTION OUTPUT ;
    USE SIGNAL ;
    ANTENNADIFFAREA 0.004232 ;
    PORT
      LAYER metal1 ;
        RECT 0.017 0.039 0.047 0.213 ;
    END
  END QN
  PIN VDD
    DIRECTION INOUT ;
    USE POWER ;
    PORT
      LAYER metal0 ;
        RECT -0.019 0.477 0.659 0.531 ;
        RECT -0.019 -0.027 0.659 0.027 ;
    END
  END VDD
  PIN VSS
    DIRECTION INOUT ;
    USE GROUND ;
    PORT
      LAYER metal0 ;
        RECT -0.019 0.225 0.659 0.279 ;
    END
  END VSS
  OBS
    LAYER metal1 ;
      RECT 0.593 0.291 0.623 0.465 ;
      RECT 0.145 0.183 0.175 0.465 ;
      RECT 0.273 0.075 0.303 0.321 ;
      RECT 0.337 0.327 0.367 0.429 ;
      RECT 0.465 0.147 0.495 0.429 ;
      RECT 0.593 0.039 0.623 0.213 ;
      RECT 0.337 0.183 0.367 0.321 ;
      RECT 0.401 0.183 0.431 0.465 ;
      RECT 0.209 0.075 0.239 0.429 ;
      RECT 0.337 0.111 0.367 0.177 ;
      RECT 0.465 0.039 0.495 0.141 ;
      RECT 0.529 0.111 0.559 0.321 ;
      RECT 0.081 0.147 0.111 0.321 ;
      RECT 0.145 0.039 0.175 0.177 ;
    LAYER metal0 ;
      RECT 0.439 0.369 0.617 0.387 ;
      RECT 0.055 0.333 0.169 0.351 ;
      RECT 0.151 0.189 0.201 0.207 ;
      RECT 0.343 0.405 0.489 0.423 ;
      RECT 0.311 0.333 0.361 0.351 ;
      RECT 0.279 0.297 0.329 0.315 ;
      RECT 0.247 0.189 0.297 0.207 ;
      RECT 0.471 0.153 0.617 0.171 ;
      RECT 0.279 0.081 0.329 0.099 ;
      RECT 0.343 0.441 0.585 0.459 ;
      RECT 0.343 0.189 0.425 0.207 ;
      RECT 0.215 0.405 0.329 0.423 ;
      RECT 0.375 0.297 0.553 0.315 ;
      RECT 0.471 0.189 0.553 0.207 ;
      RECT 0.311 0.153 0.361 0.171 ;
      RECT 0.215 0.117 0.553 0.135 ;
      RECT 0.215 0.081 0.265 0.099 ;
      RECT 0.087 0.297 0.137 0.315 ;
      RECT 0.055 0.153 0.297 0.171 ;
      RECT 0.151 0.045 0.297 0.063 ;
      RECT 0.599 0.441 0.617 0.459 ;
      RECT 0.599 0.297 0.617 0.315 ;
      RECT 0.151 0.441 0.169 0.459 ;
      RECT 0.151 0.297 0.169 0.315 ;
      RECT 0.599 0.189 0.617 0.207 ;
      RECT 0.599 0.045 0.617 0.063 ;
      RECT 0.343 0.297 0.361 0.315 ;
      RECT 0.471 0.045 0.489 0.063 ;
      RECT 0.535 0.045 0.585 0.063 ;
      RECT 0.247 0.333 0.297 0.351 ;
      RECT 0.023 0.297 0.041 0.315 ;
      RECT 0.023 0.441 0.041 0.459 ;
      RECT 0.023 0.189 0.041 0.207 ;
      RECT 0.023 0.045 0.041 0.063 ;
  END
END DFF_X1

MACRO DFF_X2
  CLASS CORE ;
  FOREIGN DFF_X2 0 0 ;
  SIZE 0.704 BY 0.504 ;
  ORIGIN 0.0 0.0 ;
  SYMMETRY X Y ;
  PIN CK
    DIRECTION INPUT ;
    USE CLOCK ;
    ANTENNAGATEAREA 0.001656 ;
    PORT
      LAYER metal1 ;
        RECT 0.593 0.039 0.623 0.069 ;
    END
  END CK
  PIN D
    DIRECTION INPUT ;
    USE SIGNAL ;
    ANTENNAGATEAREA 0.001656 ;
    PORT
      LAYER metal1 ;
        RECT 0.273 0.363 0.303 0.393 ;
    END
  END D
  PIN Q
    DIRECTION OUTPUT ;
    USE SIGNAL ;
    ANTENNADIFFAREA 0.004232 ;
    PORT
      LAYER metal1 ;
        RECT 0.081 0.291 0.111 0.465 ;
    END
  END Q
  PIN QN
    DIRECTION OUTPUT ;
    USE SIGNAL ;
    ANTENNADIFFAREA 0.004232 ;
    PORT
      LAYER metal1 ;
        RECT 0.081 0.039 0.111 0.213 ;
    END
  END QN
  PIN VDD
    DIRECTION INOUT ;
    USE POWER ;
    PORT
      LAYER metal0 ;
        RECT -0.019 0.477 0.723 0.531 ;
        RECT -0.019 -0.027 0.723 0.027 ;
    END
  END VDD
  PIN VSS
    DIRECTION INOUT ;
    USE GROUND ;
    PORT
      LAYER metal0 ;
        RECT -0.019 0.225 0.723 0.279 ;
    END
  END VSS
  OBS
    LAYER metal1 ;
      RECT 0.209 0.183 0.239 0.465 ;
      RECT 0.337 0.075 0.367 0.357 ;
      RECT 0.401 0.327 0.431 0.429 ;
      RECT 0.529 0.183 0.559 0.429 ;
      RECT 0.657 0.039 0.687 0.213 ;
      RECT 0.145 0.183 0.175 0.357 ;
      RECT 0.273 0.039 0.303 0.357 ;
      RECT 0.401 0.183 0.431 0.321 ;
      RECT 0.465 0.183 0.495 0.465 ;
      RECT 0.657 0.291 0.687 0.465 ;
      RECT 0.209 0.075 0.239 0.141 ;
      RECT 0.337 0.363 0.367 0.429 ;
      RECT 0.401 0.111 0.431 0.177 ;
      RECT 0.529 0.039 0.559 0.177 ;
      RECT 0.593 0.111 0.623 0.393 ;
    LAYER metal0 ;
      RECT 0.055 0.405 0.233 0.423 ;
      RECT 0.215 0.189 0.265 0.207 ;
      RECT 0.407 0.405 0.553 0.423 ;
      RECT 0.343 0.333 0.425 0.351 ;
      RECT 0.535 0.189 0.585 0.207 ;
      RECT 0.311 0.153 0.361 0.171 ;
      RECT 0.343 0.081 0.393 0.099 ;
      RECT 0.567 0.081 0.681 0.099 ;
      RECT 0.151 0.333 0.297 0.351 ;
      RECT 0.119 0.189 0.169 0.207 ;
      RECT 0.279 0.189 0.361 0.207 ;
      RECT 0.055 0.117 0.137 0.135 ;
      RECT 0.279 0.045 0.361 0.063 ;
      RECT 0.407 0.441 0.649 0.459 ;
      RECT 0.407 0.189 0.489 0.207 ;
      RECT 0.503 0.333 0.681 0.351 ;
      RECT 0.343 0.405 0.393 0.423 ;
      RECT 0.343 0.369 0.617 0.387 ;
      RECT 0.439 0.297 0.617 0.315 ;
      RECT 0.375 0.153 0.425 0.171 ;
      RECT 0.215 0.117 0.617 0.135 ;
      RECT 0.215 0.081 0.329 0.099 ;
      RECT 0.215 0.441 0.233 0.459 ;
      RECT 0.215 0.297 0.233 0.315 ;
      RECT 0.663 0.189 0.681 0.207 ;
      RECT 0.663 0.045 0.681 0.063 ;
      RECT 0.407 0.297 0.425 0.315 ;
      RECT 0.663 0.441 0.681 0.459 ;
      RECT 0.663 0.297 0.681 0.315 ;
      RECT 0.535 0.153 0.553 0.171 ;
      RECT 0.535 0.045 0.553 0.063 ;
      RECT 0.599 0.045 0.649 0.063 ;
      RECT 0.279 0.369 0.329 0.387 ;
      RECT 0.087 0.441 0.105 0.459 ;
      RECT 0.087 0.297 0.105 0.315 ;
      RECT 0.087 0.189 0.105 0.207 ;
      RECT 0.087 0.045 0.105 0.063 ;
  END
END DFF_X2

MACRO DFFR_X1
  CLASS CORE ;
  FOREIGN DFFR_X1 0 0 ;
  SIZE 0.704 BY 0.504 ;
  ORIGIN 0.0 0.0 ;
  SYMMETRY X Y ;
  PIN CK
    DIRECTION INPUT ;
    USE CLOCK ;
    ANTENNAGATEAREA 0.001656 ;
    PORT
      LAYER metal1 ;
        RECT 0.593 0.039 0.623 0.069 ;
    END
  END CK
  PIN D
    DIRECTION INPUT ;
    USE SIGNAL ;
    ANTENNAGATEAREA 0.001656 ;
    PORT
      LAYER metal1 ;
        RECT 0.273 0.435 0.303 0.465 ;
    END
  END D
  PIN Q
    DIRECTION OUTPUT ;
    USE SIGNAL ;
    ANTENNADIFFAREA 0.004232 ;
    PORT
      LAYER metal1 ;
        RECT 0.017 0.291 0.047 0.465 ;
    END
  END Q
  PIN QN
    DIRECTION OUTPUT ;
    USE SIGNAL ;
    ANTENNAGATEAREA 0.003312 ;
    ANTENNADIFFAREA 0.004232 ;
    PORT
      LAYER metal1 ;
        RECT 0.017 0.039 0.047 0.213 ;
        RECT 0.081 0.183 0.111 0.357 ;
    END
  END QN
  PIN RN
    DIRECTION INPUT ;
    USE SIGNAL ;
    ANTENNAGATEAREA 0.003312 ;
    PORT
      LAYER metal1 ;
        RECT 0.465 0.363 0.495 0.393 ;
        RECT 0.145 0.075 0.175 0.393 ;
    END
  END RN
  PIN VDD
    DIRECTION INOUT ;
    USE POWER ;
    PORT
      LAYER metal0 ;
        RECT -0.019 -0.027 0.723 0.027 ;
        RECT -0.019 0.477 0.723 0.531 ;
    END
  END VDD
  PIN VSS
    DIRECTION INOUT ;
    USE GROUND ;
    PORT
      LAYER metal0 ;
        RECT -0.019 0.225 0.723 0.279 ;
    END
  END VSS
  OBS
    LAYER metal1 ;
      RECT 0.209 0.327 0.239 0.429 ;
      RECT 0.529 0.039 0.559 0.355 ;
      RECT 0.401 0.111 0.431 0.177 ;
      RECT 0.273 0.075 0.303 0.357 ;
      RECT 0.657 0.039 0.687 0.213 ;
      RECT 0.337 0.075 0.367 0.429 ;
      RECT 0.209 0.039 0.239 0.177 ;
      RECT 0.657 0.291 0.687 0.465 ;
      RECT 0.401 0.183 0.431 0.465 ;
    LAYER metal0 ;
      RECT 0.279 0.117 0.553 0.135 ;
      RECT 0.375 0.153 0.425 0.171 ;
      RECT 0.279 0.081 0.329 0.099 ;
      RECT 0.343 0.081 0.681 0.099 ;
      RECT 0.311 0.189 0.361 0.207 ;
      RECT 0.209 0.153 0.361 0.171 ;
      RECT 0.215 0.045 0.361 0.063 ;
      RECT 0.119 0.045 0.233 0.063 ;
      RECT 0.535 0.189 0.553 0.207 ;
      RECT 0.407 0.189 0.489 0.207 ;
      RECT 0.535 0.045 0.553 0.063 ;
      RECT 0.663 0.045 0.681 0.063 ;
      RECT 0.663 0.189 0.681 0.207 ;
      RECT 0.407 0.405 0.553 0.423 ;
      RECT 0.343 0.441 0.649 0.459 ;
      RECT 0.375 0.333 0.553 0.351 ;
      RECT 0.503 0.297 0.681 0.315 ;
      RECT 0.343 0.405 0.393 0.423 ;
      RECT 0.215 0.405 0.329 0.423 ;
      RECT 0.311 0.333 0.361 0.351 ;
      RECT 0.343 0.297 0.425 0.315 ;
      RECT 0.663 0.441 0.681 0.459 ;
      RECT 0.215 0.333 0.297 0.351 ;
      RECT 0.599 0.045 0.649 0.063 ;
      RECT 0.247 0.441 0.297 0.459 ;
      RECT 0.023 0.297 0.041 0.315 ;
      RECT 0.023 0.441 0.041 0.459 ;
      RECT 0.215 0.189 0.265 0.207 ;
      RECT 0.023 0.189 0.233 0.207 ;
      RECT 0.023 0.045 0.105 0.063 ;
      RECT 0.055 0.333 0.111 0.351 ;
      RECT 0.439 0.369 0.489 0.387 ;
      RECT 0.151 0.369 0.457 0.387 ;
      RECT 0.055 0.081 0.169 0.099 ;
  END
END DFFR_X1

MACRO DLH_X1
  CLASS CORE ;
  FOREIGN DLH_X1 0 0 ;
  SIZE 0.512 BY 0.504 ;
  ORIGIN 0.0 0.0 ;
  SYMMETRY X Y ;
  PIN CK
    DIRECTION INPUT ;
    USE CLOCK ;
    ANTENNAGATEAREA 0.001656 ;
    PORT
      LAYER metal1 ;
        RECT 0.081 0.04 0.111 0.07 ;
    END
  END CK
  PIN D
    DIRECTION INPUT ;
    USE SIGNAL ;
    ANTENNAGATEAREA 0.001656 ;
    PORT
      LAYER metal1 ;
        RECT 0.081 0.328 0.111 0.358 ;
    END
  END D
  PIN Q
    DIRECTION OUTPUT ;
    USE SIGNAL ;
    ANTENNADIFFAREA 0.004232 ;
    PORT
      LAYER metal1 ;
        RECT 0.465 0.042 0.495 0.21 ;
    END
  END Q
  PIN QN
    DIRECTION OUTPUT ;
    USE SIGNAL ;
    ANTENNADIFFAREA 0.004232 ;
    PORT
      LAYER metal1 ;
        RECT 0.465 0.291 0.495 0.462 ;
    END
  END QN
  PIN VDD
    DIRECTION INOUT ;
    USE POWER ;
    PORT
      LAYER metal0 ;
        RECT -0.019 0.477 0.531 0.531 ;
        RECT -0.019 -0.027 0.531 0.027 ;
    END
  END VDD
  PIN VSS
    DIRECTION INOUT ;
    USE GROUND ;
    PORT
      LAYER metal0 ;
        RECT -0.019 0.225 0.531 0.279 ;
    END
  END VSS
  OBS
    LAYER metal1 ;
      RECT 0.145 0.039 0.175 0.354 ;
      RECT 0.337 0.042 0.367 0.21 ;
      RECT 0.401 0.186 0.431 0.354 ;
      RECT 0.337 0.291 0.367 0.462 ;
      RECT 0.273 0.186 0.303 0.318 ;
      RECT 0.209 0.291 0.239 0.462 ;
      RECT 0.017 0.039 0.047 0.426 ;
    LAYER metal0 ;
      RECT 0.012 0.405 0.201 0.423 ;
      RECT 0.247 0.189 0.3 0.207 ;
      RECT 0.148 0.333 0.201 0.351 ;
      RECT 0.212 0.333 0.428 0.351 ;
      RECT 0.012 0.081 0.329 0.099 ;
      RECT 0.343 0.441 0.457 0.459 ;
      RECT 0.27 0.297 0.367 0.315 ;
      RECT 0.337 0.045 0.367 0.063 ;
      RECT 0.145 0.045 0.329 0.063 ;
      RECT 0.145 0.189 0.175 0.207 ;
      RECT 0.209 0.297 0.239 0.315 ;
      RECT 0.215 0.441 0.329 0.459 ;
      RECT 0.343 0.189 0.457 0.207 ;
      RECT 0.017 0.045 0.047 0.063 ;
      RECT 0.017 0.189 0.047 0.207 ;
      RECT 0.055 0.045 0.11 0.063 ;
      RECT 0.084 0.333 0.137 0.351 ;
      RECT 0.465 0.045 0.495 0.063 ;
      RECT 0.465 0.189 0.495 0.207 ;
      RECT 0.465 0.297 0.495 0.315 ;
      RECT 0.471 0.441 0.51 0.459 ;
  END
END DLH_X1

MACRO FA_X1
  CLASS CORE ;
  FOREIGN FA_X1 0 0 ;
  SIZE 0.704 BY 0.504 ;
  ORIGIN 0.0 0.0 ;
  SYMMETRY X Y ;
  PIN A
    DIRECTION INPUT ;
    USE SIGNAL ;
    ANTENNAGATEAREA 0.006624 ;
    PORT
      LAYER metal1 ;
        RECT 0.145 0.147 0.175 0.393 ;
        RECT 0.593 0.147 0.623 0.393 ;
    END
  END A
  PIN B
    DIRECTION INPUT ;
    USE SIGNAL ;
    ANTENNAGATEAREA 0.006624 ;
    PORT
      LAYER metal1 ;
        RECT 0.081 0.111 0.111 0.321 ;
        RECT 0.529 0.075 0.559 0.321 ;
    END
  END B
  PIN CI
    DIRECTION INPUT ;
    USE SIGNAL ;
    ANTENNAGATEAREA 0.004968 ;
    PORT
      LAYER metal1 ;
        RECT 0.657 0.111 0.687 0.357 ;
    END
  END CI
  PIN CO
    DIRECTION OUTPUT ;
    USE SIGNAL ;
    ANTENNADIFFAREA 0.004232 ;
    PORT
      LAYER metal1 ;
        RECT 0.337 0.039 0.367 0.213 ;
    END
  END CO
  PIN S
    DIRECTION INPUT ;
    USE SIGNAL ;
    ANTENNADIFFAREA 0.004232 ;
    PORT
      LAYER metal1 ;
        RECT 0.273 0.327 0.303 0.465 ;
    END
  END S
  PIN VDD
    DIRECTION INOUT ;
    USE POWER ;
    PORT
      LAYER metal0 ;
        RECT -0.019 0.477 0.723 0.531 ;
        RECT -0.019 -0.027 0.723 0.027 ;
    END
  END VDD
  PIN VSS
    DIRECTION INOUT ;
    USE GROUND ;
    PORT
      LAYER metal0 ;
        RECT -0.019 0.225 0.723 0.279 ;
    END
  END VSS
  OBS
    LAYER metal1 ;
      RECT 0.209 0.039 0.239 0.465 ;
      RECT 0.401 0.039 0.431 0.465 ;
    LAYER metal0 ;
      RECT 0.471 0.189 0.617 0.207 ;
      RECT 0.215 0.153 0.457 0.171 ;
      RECT 0.023 0.045 0.169 0.063 ;
      RECT 0.471 0.045 0.617 0.063 ;
      RECT 0.311 0.405 0.425 0.423 ;
      RECT 0.215 0.441 0.233 0.459 ;
      RECT 0.215 0.333 0.233 0.351 ;
      RECT 0.215 0.189 0.233 0.207 ;
      RECT 0.215 0.045 0.233 0.063 ;
      RECT 0.023 0.189 0.169 0.207 ;
      RECT 0.407 0.441 0.425 0.459 ;
      RECT 0.407 0.333 0.425 0.351 ;
      RECT 0.407 0.189 0.425 0.207 ;
      RECT 0.407 0.045 0.425 0.063 ;
      RECT 0.151 0.369 0.617 0.387 ;
      RECT 0.119 0.153 0.169 0.171 ;
      RECT 0.599 0.153 0.649 0.171 ;
      RECT 0.087 0.297 0.553 0.315 ;
      RECT 0.055 0.117 0.105 0.135 ;
      RECT 0.535 0.081 0.585 0.099 ;
      RECT 0.439 0.333 0.681 0.351 ;
      RECT 0.183 0.117 0.681 0.135 ;
      RECT 0.343 0.045 0.361 0.063 ;
      RECT 0.343 0.189 0.361 0.207 ;
      RECT 0.279 0.333 0.297 0.351 ;
      RECT 0.279 0.441 0.297 0.459 ;
  END
END FA_X1

MACRO HA_X1
  CLASS CORE ;
  FOREIGN HA_X1 0 0 ;
  SIZE 0.384 BY 0.504 ;
  ORIGIN 0.0 0.0 ;
  SYMMETRY X Y ;
  PIN A
    DIRECTION INPUT ;
    USE SIGNAL ;
    ANTENNAGATEAREA 0.004968 ;
    PORT
      LAYER metal1 ;
        RECT 0.209 0.147 0.239 0.357 ;
    END
  END A
  PIN B
    DIRECTION INPUT ;
    USE SIGNAL ;
    ANTENNAGATEAREA 0.004968 ;
    PORT
      LAYER metal1 ;
        RECT 0.273 0.111 0.303 0.393 ;
    END
  END B
  PIN CO
    DIRECTION OUTPUT ;
    USE SIGNAL ;
    ANTENNADIFFAREA 0.004232 ;
    PORT
      LAYER metal1 ;
        RECT 0.337 0.327 0.367 0.465 ;
    END
  END CO
  PIN S
    DIRECTION INPUT ;
    USE SIGNAL ;
    ANTENNADIFFAREA 0.006348 ;
    PORT
      LAYER metal1 ;
        RECT 0.145 0.291 0.175 0.465 ;
    END
  END S
  PIN VDD
    DIRECTION INOUT ;
    USE POWER ;
    PORT
      LAYER metal0 ;
        RECT -0.019 0.477 0.403 0.531 ;
        RECT -0.019 -0.027 0.403 0.027 ;
    END
  END VDD
  PIN VSS
    DIRECTION INOUT ;
    USE GROUND ;
    PORT
      LAYER metal0 ;
        RECT -0.019 0.225 0.403 0.279 ;
    END
  END VSS
  OBS
    LAYER metal1 ;
      RECT 0.081 0.399 0.111 0.465 ;
      RECT 0.209 0.399 0.239 0.465 ;
      RECT 0.017 0.039 0.047 0.357 ;
      RECT 0.081 0.183 0.111 0.357 ;
      RECT 0.273 0.039 0.303 0.105 ;
      RECT 0.337 0.039 0.367 0.321 ;
    LAYER metal0 ;
      RECT 0.087 0.405 0.233 0.423 ;
      RECT 0.023 0.333 0.105 0.351 ;
      RECT 0.087 0.189 0.169 0.207 ;
      RECT 0.311 0.297 0.361 0.315 ;
      RECT 0.279 0.081 0.361 0.099 ;
      RECT 0.215 0.045 0.297 0.063 ;
      RECT 0.087 0.441 0.105 0.459 ;
      RECT 0.215 0.441 0.233 0.459 ;
      RECT 0.023 0.189 0.041 0.207 ;
      RECT 0.023 0.045 0.041 0.063 ;
      RECT 0.343 0.189 0.361 0.207 ;
      RECT 0.343 0.045 0.361 0.063 ;
      RECT 0.119 0.153 0.329 0.171 ;
      RECT 0.183 0.333 0.233 0.351 ;
      RECT 0.119 0.369 0.297 0.387 ;
      RECT 0.055 0.117 0.297 0.135 ;
      RECT 0.279 0.441 0.361 0.459 ;
      RECT 0.279 0.333 0.361 0.351 ;
      RECT 0.151 0.441 0.169 0.459 ;
      RECT 0.023 0.297 0.233 0.315 ;
  END
END HA_X1

MACRO INV_X1
  CLASS CORE ;
  FOREIGN INV_X1 0 0 ;
  SIZE 0.128 BY 0.252 ;
  ORIGIN 0.0 0.0 ;
  SYMMETRY X Y ;
  PIN A
    DIRECTION INPUT ;
    USE SIGNAL ;
    ANTENNAGATEAREA 0.001656 ;
    PORT
      LAYER metal1 ;
        RECT 0.017 0.183 0.047 0.213 ;
    END
  END A
  PIN ZN
    DIRECTION OUTPUT ;
    USE SIGNAL ;
    ANTENNADIFFAREA 0.004232 ;
    PORT
      LAYER metal1 ;
        RECT 0.081 0.039 0.111 0.213 ;
    END
  END ZN
  PIN VDD
    DIRECTION INOUT ;
    USE POWER ;
    PORT
      LAYER metal0 ;
        RECT -0.019 0.225 0.147 0.279 ;
    END
  END VDD
  PIN VSS
    DIRECTION INOUT ;
    USE GROUND ;
    PORT
      LAYER metal0 ;
        RECT -0.019 -0.027 0.147 0.027 ;
    END
  END VSS
  OBS
    LAYER metal0 ;
      RECT 0.023 0.189 0.073 0.207 ;
      RECT 0.087 0.189 0.105 0.207 ;
      RECT 0.087 0.045 0.105 0.063 ;
  END
END INV_X1

MACRO INV_X2
  CLASS CORE ;
  FOREIGN INV_X2 0 0 ;
  SIZE 0.192 BY 0.252 ;
  ORIGIN 0.0 0.0 ;
  SYMMETRY X Y ;
  PIN A
    DIRECTION INPUT ;
    USE SIGNAL ;
    ANTENNAGATEAREA 0.003312 ;
    PORT
      LAYER metal1 ;
        RECT 0.081 0.075 0.111 0.105 ;
    END
  END A
  PIN ZN
    DIRECTION OUTPUT ;
    USE SIGNAL ;
    ANTENNADIFFAREA 0.004232 ;
    PORT
      LAYER metal1 ;
        RECT 0.145 0.039 0.175 0.213 ;
    END
  END ZN
  PIN VDD
    DIRECTION INOUT ;
    USE POWER ;
    PORT
      LAYER metal0 ;
        RECT 0.045 0.225 0.211 0.279 ;
        RECT -0.019 0.225 0.147 0.279 ;
    END
  END VDD
  PIN VSS
    DIRECTION INOUT ;
    USE GROUND ;
    PORT
      LAYER metal0 ;
        RECT 0.045 -0.027 0.211 0.027 ;
        RECT -0.019 -0.027 0.147 0.027 ;
    END
  END VSS
  OBS
    LAYER metal0 ;
      RECT 0.087 0.081 0.137 0.099 ;
      RECT 0.055 0.081 0.105 0.099 ;
      RECT 0.087 0.045 0.169 0.063 ;
      RECT 0.087 0.189 0.169 0.207 ;
  END
END INV_X2

MACRO INV_X4
  CLASS CORE ;
  FOREIGN INV_X4 0 0 ;
  SIZE 0.32 BY 0.252 ;
  ORIGIN 0.0 0.0 ;
  SYMMETRY X Y ;
  PIN A
    DIRECTION INPUT ;
    USE SIGNAL ;
    ANTENNAGATEAREA 0.006624 ;
    PORT
      LAYER metal1 ;
        RECT 0.081 0.147 0.111 0.177 ;
    END
  END A
  PIN ZN
    DIRECTION OUTPUT ;
    USE SIGNAL ;
    ANTENNADIFFAREA 0.012696 ;
    PORT
      LAYER metal1 ;
        RECT 0.017 0.039 0.047 0.213 ;
        RECT 0.145 0.039 0.175 0.213 ;
        RECT 0.273 0.039 0.303 0.213 ;
    END
  END ZN
  PIN VDD
    DIRECTION INOUT ;
    USE POWER ;
    PORT
      LAYER metal0 ;
        RECT -0.019 0.225 0.339 0.279 ;
    END
  END VDD
  PIN VSS
    DIRECTION INOUT ;
    USE GROUND ;
    PORT
      LAYER metal0 ;
        RECT -0.019 -0.027 0.339 0.027 ;
    END
  END VSS
  OBS
    LAYER metal0 ;
      RECT 0.055 0.153 0.265 0.171 ;
      RECT 0.023 0.189 0.041 0.207 ;
      RECT 0.023 0.045 0.041 0.063 ;
      RECT 0.023 0.117 0.297 0.135 ;
      RECT 0.279 0.045 0.297 0.063 ;
      RECT 0.279 0.189 0.297 0.207 ;
      RECT 0.151 0.189 0.169 0.207 ;
      RECT 0.151 0.045 0.169 0.063 ;
  END
END INV_X4

MACRO INV_X8
  CLASS CORE ;
  FOREIGN INV_X8 0 0 ;
  SIZE 0.576 BY 0.252 ;
  ORIGIN 0.0 0.0 ;
  SYMMETRY X Y ;
  PIN A
    DIRECTION INPUT ;
    USE SIGNAL ;
    ANTENNAGATEAREA 0.013248 ;
    PORT
      LAYER metal1 ;
        RECT 0.081 0.147 0.111 0.177 ;
    END
  END A
  PIN ZN
    DIRECTION OUTPUT ;
    USE SIGNAL ;
    ANTENNADIFFAREA 0.021160 ;
    PORT
      LAYER metal1 ;
        RECT 0.017 0.039 0.047 0.213 ;
        RECT 0.529 0.039 0.559 0.213 ;
        RECT 0.145 0.039 0.175 0.213 ;
        RECT 0.401 0.039 0.431 0.213 ;
        RECT 0.273 0.039 0.303 0.213 ;
    END
  END ZN
  PIN VDD
    DIRECTION INOUT ;
    USE POWER ;
    PORT
      LAYER metal0 ;
        RECT -0.019 0.225 0.339 0.279 ;
        RECT 0.237 0.225 0.595 0.279 ;
    END
  END VDD
  PIN VSS
    DIRECTION INOUT ;
    USE GROUND ;
    PORT
      LAYER metal0 ;
        RECT 0.237 -0.027 0.595 0.027 ;
        RECT -0.019 -0.027 0.339 0.027 ;
    END
  END VSS
  OBS
    LAYER metal0 ;
      RECT 0.311 0.153 0.521 0.171 ;
      RECT 0.055 0.153 0.313 0.171 ;
      RECT 0.023 0.189 0.041 0.207 ;
      RECT 0.023 0.045 0.041 0.063 ;
      RECT 0.023 0.117 0.297 0.135 ;
      RECT 0.279 0.117 0.553 0.135 ;
      RECT 0.407 0.045 0.425 0.063 ;
      RECT 0.279 0.189 0.297 0.207 ;
      RECT 0.279 0.045 0.297 0.063 ;
      RECT 0.151 0.189 0.169 0.207 ;
      RECT 0.407 0.189 0.425 0.207 ;
      RECT 0.151 0.045 0.169 0.063 ;
      RECT 0.535 0.045 0.553 0.063 ;
      RECT 0.535 0.189 0.553 0.207 ;
  END
END INV_X8

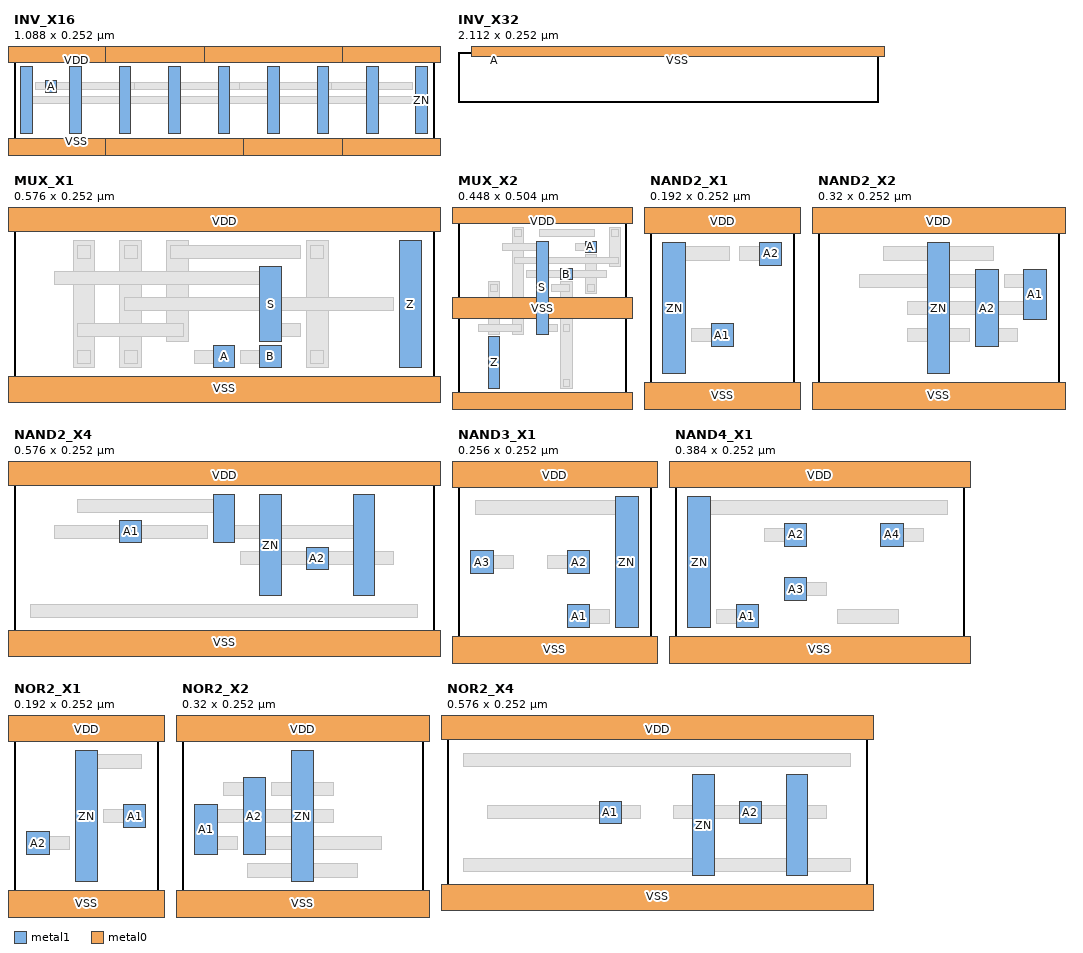
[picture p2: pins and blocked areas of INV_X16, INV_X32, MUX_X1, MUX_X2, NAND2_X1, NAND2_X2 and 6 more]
MACRO INV_X16
  CLASS CORE ;
  FOREIGN INV_X16 0 0 ;
  SIZE 1.088 BY 0.252 ;
  ORIGIN 0.0 0.0 ;
  SYMMETRY X Y ;
  PIN A
    DIRECTION INPUT ;
    USE SIGNAL ;
    ANTENNAGATEAREA 0.026496 ;
    PORT
      LAYER metal1 ;
        RECT 0.081 0.147 0.111 0.177 ;
    END
  END A
  PIN ZN
    DIRECTION OUTPUT ;
    USE SIGNAL ;
    ANTENNADIFFAREA 0.038088 ;
    PORT
      LAYER metal1 ;
        RECT 0.017 0.039 0.047 0.213 ;
        RECT 1.041 0.039 1.071 0.213 ;
        RECT 0.657 0.039 0.687 0.213 ;
        RECT 0.913 0.039 0.943 0.213 ;
        RECT 0.401 0.039 0.431 0.213 ;
        RECT 0.145 0.039 0.175 0.213 ;
        RECT 0.273 0.039 0.303 0.213 ;
        RECT 0.785 0.039 0.815 0.213 ;
        RECT 0.529 0.039 0.559 0.213 ;
    END
  END ZN
  PIN VDD
    DIRECTION INOUT ;
    USE POWER ;
    PORT
      LAYER metal0 ;
        RECT -0.019 0.225 0.339 0.279 ;
        RECT 0.237 0.225 0.595 0.279 ;
        RECT 0.749 0.225 1.107 0.279 ;
        RECT 0.493 0.225 0.851 0.279 ;
    END
  END VDD
  PIN VSS
    DIRECTION INOUT ;
    USE GROUND ;
    PORT
      LAYER metal0 ;
        RECT 0.749 -0.027 1.107 0.027 ;
        RECT 0.493 -0.027 0.851 0.027 ;
        RECT 0.237 -0.027 0.595 0.027 ;
        RECT -0.019 -0.027 0.339 0.027 ;
    END
  END VSS
  OBS
    LAYER metal0 ;
      RECT 0.567 0.153 0.825 0.171 ;
      RECT 0.823 0.153 1.033 0.171 ;
      RECT 0.311 0.153 0.585 0.171 ;
      RECT 0.055 0.153 0.313 0.171 ;
      RECT 0.535 0.117 0.809 0.135 ;
      RECT 0.023 0.189 0.041 0.207 ;
      RECT 0.023 0.045 0.041 0.063 ;
      RECT 0.279 0.117 0.553 0.135 ;
      RECT 0.023 0.117 0.297 0.135 ;
      RECT 0.791 0.117 1.065 0.135 ;
      RECT 0.663 0.189 0.681 0.207 ;
      RECT 0.407 0.045 0.425 0.063 ;
      RECT 1.047 0.189 1.065 0.207 ;
      RECT 0.279 0.189 0.297 0.207 ;
      RECT 0.535 0.045 0.553 0.063 ;
      RECT 1.047 0.045 1.065 0.063 ;
      RECT 0.791 0.189 0.809 0.207 ;
      RECT 0.279 0.045 0.297 0.063 ;
      RECT 0.791 0.045 0.809 0.063 ;
      RECT 0.151 0.189 0.169 0.207 ;
      RECT 0.407 0.189 0.425 0.207 ;
      RECT 0.151 0.045 0.169 0.063 ;
      RECT 0.919 0.045 0.937 0.063 ;
      RECT 0.919 0.189 0.937 0.207 ;
      RECT 0.663 0.045 0.681 0.063 ;
      RECT 0.535 0.189 0.553 0.207 ;
  END
END INV_X16

MACRO INV_X32
  CLASS CORE ;
  ORIGIN 0 0 ;
  FOREIGN INV_X32 0 0 ;
  SIZE 2.112 BY 0.252 ;
  PIN VDD
    DIRECTION INOUT ;
    USE POWER ;
    PORT
      LAYER metal0 ;
        RECT 0.067 0.479 2.217 0.533 ;
    END
  END VDD
  PIN VSS
    DIRECTION INOUT ;
    USE GROUND ;
    PORT
      LAYER metal0 ;
        RECT 0.067 0.227 2.217 0.281 ;
    END
  END VSS
  PIN A
    DIRECTION INOUT ;
    USE SIGNAL ;
    PORT
      LAYER metal1 ;
        RECT 0.167 0.401 0.197 0.431 ;
    END
  END A
  PIN ZN
    DIRECTION INOUT ;
    USE SIGNAL ;
    PORT
      LAYER metal1 ;
        RECT 0.103 0.293 0.133 0.467 ;
    END
  END ZN
  OBS
    LAYER metal1 ;
      RECT 0.231 0.293 0.261 0.467 ;
      RECT 0.359 0.293 0.389 0.467 ;
      RECT 0.487 0.293 0.517 0.467 ;
      RECT 0.615 0.293 0.645 0.467 ;
      RECT 0.743 0.293 0.773 0.467 ;
      RECT 0.871 0.293 0.901 0.467 ;
      RECT 0.999 0.293 1.029 0.467 ;
      RECT 1.127 0.293 1.157 0.467 ;
      RECT 1.255 0.293 1.285 0.467 ;
      RECT 1.383 0.293 1.413 0.467 ;
      RECT 1.511 0.293 1.541 0.467 ;
      RECT 1.639 0.293 1.669 0.467 ;
      RECT 1.767 0.293 1.797 0.467 ;
      RECT 1.895 0.293 1.925 0.467 ;
      RECT 2.023 0.293 2.053 0.467 ;
      RECT 2.151 0.293 2.181 0.467 ;
    LAYER metal0 ;
      RECT 0.109 0.299 0.127 0.317 ;
      RECT 0.237 0.299 0.255 0.317 ;
      RECT 0.365 0.299 0.383 0.317 ;
      RECT 0.493 0.299 0.511 0.317 ;
      RECT 0.621 0.299 0.639 0.317 ;
      RECT 0.749 0.299 0.767 0.317 ;
      RECT 0.877 0.299 0.895 0.317 ;
      RECT 1.005 0.299 1.023 0.317 ;
      RECT 1.133 0.299 1.151 0.317 ;
      RECT 1.261 0.299 1.279 0.317 ;
      RECT 1.389 0.299 1.407 0.317 ;
      RECT 1.517 0.299 1.535 0.317 ;
      RECT 1.645 0.299 1.663 0.317 ;
      RECT 1.773 0.299 1.791 0.317 ;
      RECT 1.901 0.299 1.919 0.317 ;
      RECT 2.029 0.299 2.047 0.317 ;
      RECT 2.157 0.299 2.175 0.317 ;
      RECT 0.109 0.371 2.175 0.389 ;
      RECT 0.141 0.407 2.143 0.425 ;
      RECT 0.109 0.443 0.127 0.461 ;
      RECT 0.237 0.443 0.255 0.461 ;
      RECT 0.365 0.443 0.383 0.461 ;
      RECT 0.493 0.443 0.511 0.461 ;
      RECT 0.621 0.443 0.639 0.461 ;
      RECT 0.749 0.443 0.767 0.461 ;
      RECT 0.877 0.443 0.895 0.461 ;
      RECT 1.005 0.443 1.023 0.461 ;
      RECT 1.133 0.443 1.151 0.461 ;
      RECT 1.261 0.443 1.279 0.461 ;
      RECT 1.389 0.443 1.407 0.461 ;
      RECT 1.517 0.443 1.535 0.461 ;
      RECT 1.645 0.443 1.663 0.461 ;
      RECT 1.773 0.443 1.791 0.461 ;
      RECT 1.901 0.443 1.919 0.461 ;
      RECT 2.029 0.443 2.047 0.461 ;
      RECT 2.157 0.443 2.175 0.461 ;
  END
END INV_X32


MACRO MUX_X1
  CLASS CORE ;
  FOREIGN MUX_X1 0 0 ;
  SIZE 0.576 BY 0.252 ;
  ORIGIN 0.0 0.0 ;
  SYMMETRY X Y ;
  PIN A
    DIRECTION INPUT ;
    USE SIGNAL ;
    ANTENNAGATEAREA 0.001656 ;
    PORT
      LAYER metal1 ;
        RECT 0.273 0.039 0.303 0.069 ;
    END
  END A
  PIN B
    DIRECTION INPUT ;
    USE SIGNAL ;
    ANTENNAGATEAREA 0.001656 ;
    PORT
      LAYER metal1 ;
        RECT 0.337 0.039 0.367 0.069 ;
    END
  END B
  PIN S
    DIRECTION INPUT ;
    USE SIGNAL ;
    ANTENNAGATEAREA 0.003312 ;
    PORT
      LAYER metal1 ;
        RECT 0.337 0.075 0.367 0.177 ;
    END
  END S
  PIN Z
    DIRECTION OUTPUT ;
    USE SIGNAL ;
    ANTENNADIFFAREA 0.004232 ;
    PORT
      LAYER metal1 ;
        RECT 0.529 0.039 0.559 0.213 ;
    END
  END Z
  PIN VDD
    DIRECTION INOUT ;
    USE POWER ;
    PORT
      LAYER metal0 ;
        RECT -0.019 0.225 0.595 0.279 ;
    END
  END VDD
  PIN VSS
    DIRECTION INOUT ;
    USE GROUND ;
    PORT
      LAYER metal0 ;
        RECT -0.019 -0.027 0.595 0.027 ;
    END
  END VSS
  OBS
    LAYER metal1 ;
      RECT 0.081 0.039 0.111 0.213 ;
      RECT 0.209 0.075 0.239 0.213 ;
      RECT 0.145 0.039 0.175 0.213 ;
      RECT 0.401 0.039 0.431 0.213 ;
    LAYER metal0 ;
      RECT 0.215 0.189 0.393 0.207 ;
      RECT 0.087 0.081 0.233 0.099 ;
      RECT 0.151 0.117 0.521 0.135 ;
      RECT 0.087 0.189 0.105 0.207 ;
      RECT 0.087 0.045 0.105 0.063 ;
      RECT 0.151 0.189 0.169 0.207 ;
      RECT 0.407 0.189 0.425 0.207 ;
      RECT 0.151 0.045 0.169 0.063 ;
      RECT 0.407 0.045 0.425 0.063 ;
      RECT 0.247 0.045 0.297 0.063 ;
      RECT 0.311 0.045 0.361 0.063 ;
      RECT 0.343 0.081 0.393 0.099 ;
      RECT 0.055 0.153 0.361 0.171 ;
      RECT 0.535 0.045 0.553 0.063 ;
      RECT 0.535 0.189 0.553 0.207 ;
  END
END MUX_X1

MACRO MUX_X2
  CLASS CORE ;
  FOREIGN MUX_X2 0 0 ;
  SIZE 0.448 BY 0.504 ;
  ORIGIN 0.0 0.0 ;
  SYMMETRY X Y ;
  PIN A
    DIRECTION INPUT ;
    USE SIGNAL ;
    ANTENNAGATEAREA 0.001656 ;
    PORT
      LAYER metal1 ;
        RECT 0.337 0.399 0.367 0.429 ;
    END
  END A
  PIN B
    DIRECTION INPUT ;
    USE SIGNAL ;
    ANTENNAGATEAREA 0.002484 ;
    PORT
      LAYER metal1 ;
        RECT 0.273 0.327 0.303 0.357 ;
    END
  END B
  PIN S
    DIRECTION INPUT ;
    USE SIGNAL ;
    ANTENNAGATEAREA 0.004140 ;
    PORT
      LAYER metal1 ;
        RECT 0.209 0.183 0.239 0.429 ;
    END
  END S
  PIN Z
    DIRECTION OUTPUT ;
    USE SIGNAL ;
    ANTENNADIFFAREA 0.004232 ;
    PORT
      LAYER metal1 ;
        RECT 0.081 0.039 0.111 0.177 ;
    END
  END Z
  PIN VDD
    DIRECTION INOUT ;
    USE POWER ;
    PORT
      LAYER metal0 ;
        RECT -0.019 0.477 0.467 0.531 ;
        RECT -0.019 -0.027 0.467 0.027 ;
    END
  END VDD
  PIN VSS
    DIRECTION INOUT ;
    USE GROUND ;
    PORT
      LAYER metal0 ;
        RECT -0.019 0.225 0.467 0.279 ;
    END
  END VSS
  OBS
    LAYER metal1 ;
      RECT 0.081 0.183 0.111 0.321 ;
      RECT 0.145 0.183 0.175 0.465 ;
      RECT 0.337 0.291 0.367 0.393 ;
      RECT 0.401 0.363 0.431 0.465 ;
      RECT 0.273 0.039 0.303 0.321 ;
    LAYER metal0 ;
      RECT 0.151 0.369 0.425 0.387 ;
      RECT 0.055 0.189 0.169 0.207 ;
      RECT 0.247 0.297 0.297 0.315 ;
      RECT 0.215 0.441 0.361 0.459 ;
      RECT 0.151 0.441 0.169 0.459 ;
      RECT 0.407 0.441 0.425 0.459 ;
      RECT 0.087 0.297 0.105 0.315 ;
      RECT 0.343 0.297 0.361 0.315 ;
      RECT 0.279 0.189 0.297 0.207 ;
      RECT 0.279 0.045 0.297 0.063 ;
      RECT 0.311 0.405 0.361 0.423 ;
      RECT 0.183 0.333 0.393 0.351 ;
      RECT 0.215 0.189 0.265 0.207 ;
      RECT 0.119 0.405 0.233 0.423 ;
      RECT 0.087 0.153 0.105 0.171 ;
      RECT 0.087 0.045 0.105 0.063 ;
  END
END MUX_X2

MACRO NAND2_X1
  CLASS CORE ;
  FOREIGN NAND2_X1 0 0 ;
  SIZE 0.192 BY 0.252 ;
  ORIGIN 0.0 0.0 ;
  SYMMETRY X Y ;
  PIN A1
    DIRECTION INPUT ;
    USE SIGNAL ;
    ANTENNAGATEAREA 0.001656 ;
    PORT
      LAYER metal1 ;
        RECT 0.081 0.075 0.111 0.105 ;
    END
  END A1
  PIN A2
    DIRECTION INPUT ;
    USE SIGNAL ;
    ANTENNAGATEAREA 0.001656 ;
    PORT
      LAYER metal1 ;
        RECT 0.145 0.183 0.175 0.213 ;
    END
  END A2
  PIN ZN
    DIRECTION OUTPUT ;
    USE SIGNAL ;
    ANTENNADIFFAREA 0.004232 ;
    PORT
      LAYER metal1 ;
        RECT 0.017 0.039 0.047 0.213 ;
    END
  END ZN
  PIN VDD
    DIRECTION INOUT ;
    USE POWER ;
    PORT
      LAYER metal0 ;
        RECT -0.019 0.225 0.211 0.279 ;
    END
  END VDD
  PIN VSS
    DIRECTION INOUT ;
    USE GROUND ;
    PORT
      LAYER metal0 ;
        RECT -0.019 -0.027 0.211 0.027 ;
    END
  END VSS
  OBS
    LAYER metal0 ;
      RECT 0.055 0.081 0.105 0.099 ;
      RECT 0.119 0.189 0.169 0.207 ;
      RECT 0.023 0.045 0.041 0.063 ;
      RECT 0.023 0.189 0.105 0.207 ;
  END
END NAND2_X1

MACRO NAND2_X2
  CLASS CORE ;
  FOREIGN NAND2_X2 0 0 ;
  SIZE 0.32 BY 0.252 ;
  ORIGIN 0.0 0.0 ;
  SYMMETRY X Y ;
  PIN A1
    DIRECTION INPUT ;
    USE SIGNAL ;
    ANTENNAGATEAREA 0.002484 ;
    PORT
      LAYER metal1 ;
        RECT 0.273 0.111 0.303 0.177 ;
    END
  END A1
  PIN A2
    DIRECTION INPUT ;
    USE SIGNAL ;
    ANTENNAGATEAREA 0.003312 ;
    PORT
      LAYER metal1 ;
        RECT 0.209 0.075 0.239 0.177 ;
    END
  END A2
  PIN ZN
    DIRECTION OUTPUT ;
    USE SIGNAL ;
    ANTENNADIFFAREA 0.006348 ;
    PORT
      LAYER metal1 ;
        RECT 0.145 0.039 0.175 0.213 ;
    END
  END ZN
  PIN VDD
    DIRECTION INOUT ;
    USE POWER ;
    PORT
      LAYER metal0 ;
        RECT -0.019 0.225 0.339 0.279 ;
    END
  END VDD
  PIN VSS
    DIRECTION INOUT ;
    USE GROUND ;
    PORT
      LAYER metal0 ;
        RECT -0.019 -0.027 0.339 0.027 ;
    END
  END VSS
  OBS
    LAYER metal0 ;
      RECT 0.119 0.081 0.201 0.099 ;
      RECT 0.119 0.117 0.297 0.135 ;
      RECT 0.247 0.153 0.297 0.171 ;
      RECT 0.215 0.081 0.265 0.099 ;
      RECT 0.055 0.153 0.233 0.171 ;
      RECT 0.087 0.189 0.233 0.207 ;
      RECT 0.151 0.045 0.169 0.063 ;
  END
END NAND2_X2

MACRO NAND2_X4
  CLASS CORE ;
  FOREIGN NAND2_X4 0 0 ;
  SIZE 0.576 BY 0.252 ;
  ORIGIN 0.0 0.0 ;
  SYMMETRY X Y ;
  PIN A1
    DIRECTION INPUT ;
    USE SIGNAL ;
    ANTENNAGATEAREA 0.006624 ;
    PORT
      LAYER metal1 ;
        RECT 0.145 0.147 0.175 0.177 ;
    END
  END A1
  PIN A2
    DIRECTION INPUT ;
    USE SIGNAL ;
    ANTENNAGATEAREA 0.006624 ;
    PORT
      LAYER metal1 ;
        RECT 0.401 0.111 0.431 0.141 ;
    END
  END A2
  PIN ZN
    DIRECTION OUTPUT ;
    USE SIGNAL ;
    ANTENNADIFFAREA 0.012696 ;
    PORT
      LAYER metal1 ;
        RECT 0.273 0.147 0.303 0.213 ;
        RECT 0.337 0.075 0.367 0.213 ;
        RECT 0.465 0.075 0.495 0.213 ;
    END
  END ZN
  PIN VDD
    DIRECTION INOUT ;
    USE POWER ;
    PORT
      LAYER metal0 ;
        RECT -0.019 0.225 0.595 0.279 ;
    END
  END VDD
  PIN VSS
    DIRECTION INOUT ;
    USE GROUND ;
    PORT
      LAYER metal0 ;
        RECT -0.019 -0.027 0.595 0.027 ;
    END
  END VSS
  OBS
    LAYER metal0 ;
      RECT 0.023 0.045 0.553 0.063 ;
      RECT 0.055 0.153 0.265 0.171 ;
      RECT 0.311 0.117 0.521 0.135 ;
      RECT 0.279 0.153 0.489 0.171 ;
      RECT 0.087 0.189 0.297 0.207 ;
      RECT 0.343 0.081 0.361 0.099 ;
      RECT 0.343 0.189 0.361 0.207 ;
      RECT 0.471 0.081 0.489 0.099 ;
      RECT 0.471 0.189 0.489 0.207 ;
  END
END NAND2_X4

MACRO NAND3_X1
  CLASS CORE ;
  FOREIGN NAND3_X1 0 0 ;
  SIZE 0.256 BY 0.252 ;
  ORIGIN 0.0 0.0 ;
  SYMMETRY X Y ;
  PIN A1
    DIRECTION INPUT ;
    USE SIGNAL ;
    ANTENNAGATEAREA 0.001656 ;
    PORT
      LAYER metal1 ;
        RECT 0.145 0.039 0.175 0.069 ;
    END
  END A1
  PIN A2
    DIRECTION INPUT ;
    USE SIGNAL ;
    ANTENNAGATEAREA 0.001656 ;
    PORT
      LAYER metal1 ;
        RECT 0.145 0.111 0.175 0.141 ;
    END
  END A2
  PIN A3
    DIRECTION INPUT ;
    USE SIGNAL ;
    ANTENNAGATEAREA 0.001656 ;
    PORT
      LAYER metal1 ;
        RECT 0.017 0.111 0.047 0.141 ;
    END
  END A3
  PIN ZN
    DIRECTION OUTPUT ;
    USE SIGNAL ;
    ANTENNADIFFAREA 0.006348 ;
    PORT
      LAYER metal1 ;
        RECT 0.209 0.039 0.239 0.213 ;
    END
  END ZN
  PIN VDD
    DIRECTION INOUT ;
    USE POWER ;
    PORT
      LAYER metal0 ;
        RECT -0.019 0.225 0.275 0.279 ;
    END
  END VDD
  PIN VSS
    DIRECTION INOUT ;
    USE GROUND ;
    PORT
      LAYER metal0 ;
        RECT -0.019 -0.027 0.275 0.027 ;
    END
  END VSS
  OBS
    LAYER metal0 ;
      RECT 0.151 0.045 0.201 0.063 ;
      RECT 0.119 0.117 0.169 0.135 ;
      RECT 0.023 0.117 0.073 0.135 ;
      RECT 0.215 0.045 0.233 0.063 ;
      RECT 0.023 0.189 0.233 0.207 ;
  END
END NAND3_X1

MACRO NAND4_X1
  CLASS CORE ;
  FOREIGN NAND4_X1 0 0 ;
  SIZE 0.384 BY 0.252 ;
  ORIGIN 0.0 0.0 ;
  SYMMETRY X Y ;
  PIN A1
    DIRECTION INPUT ;
    USE SIGNAL ;
    ANTENNAGATEAREA 0.001656 ;
    PORT
      LAYER metal1 ;
        RECT 0.081 0.039 0.111 0.069 ;
    END
  END A1
  PIN A2
    DIRECTION INPUT ;
    USE SIGNAL ;
    ANTENNAGATEAREA 0.001656 ;
    PORT
      LAYER metal1 ;
        RECT 0.145 0.147 0.175 0.177 ;
    END
  END A2
  PIN A3
    DIRECTION INPUT ;
    USE SIGNAL ;
    ANTENNAGATEAREA 0.001656 ;
    PORT
      LAYER metal1 ;
        RECT 0.145 0.075 0.175 0.105 ;
    END
  END A3
  PIN A4
    DIRECTION INPUT ;
    USE SIGNAL ;
    ANTENNAGATEAREA 0.001656 ;
    PORT
      LAYER metal1 ;
        RECT 0.273 0.147 0.303 0.177 ;
    END
  END A4
  PIN ZN
    DIRECTION OUTPUT ;
    USE SIGNAL ;
    ANTENNADIFFAREA 0.008464 ;
    PORT
      LAYER metal1 ;
        RECT 0.017 0.039 0.047 0.213 ;
    END
  END ZN
  PIN VDD
    DIRECTION INOUT ;
    USE POWER ;
    PORT
      LAYER metal0 ;
        RECT -0.019 0.225 0.403 0.279 ;
    END
  END VDD
  PIN VSS
    DIRECTION INOUT ;
    USE GROUND ;
    PORT
      LAYER metal0 ;
        RECT -0.019 -0.027 0.403 0.027 ;
    END
  END VSS
  OBS
    LAYER metal0 ;
      RECT 0.215 0.045 0.297 0.063 ;
      RECT 0.055 0.045 0.105 0.063 ;
      RECT 0.119 0.153 0.169 0.171 ;
      RECT 0.151 0.081 0.201 0.099 ;
      RECT 0.279 0.153 0.329 0.171 ;
      RECT 0.023 0.045 0.041 0.063 ;
      RECT 0.023 0.189 0.361 0.207 ;
  END
END NAND4_X1

MACRO NOR2_X1
  CLASS CORE ;
  FOREIGN NOR2_X1 0 0 ;
  SIZE 0.192 BY 0.252 ;
  ORIGIN 0.0 0.0 ;
  SYMMETRY X Y ;
  PIN A1
    DIRECTION INPUT ;
    USE SIGNAL ;
    ANTENNAGATEAREA 0.001656 ;
    PORT
      LAYER metal1 ;
        RECT 0.145 0.111 0.175 0.141 ;
    END
  END A1
  PIN A2
    DIRECTION INPUT ;
    USE SIGNAL ;
    ANTENNAGATEAREA 0.001656 ;
    PORT
      LAYER metal1 ;
        RECT 0.017 0.075 0.047 0.105 ;
    END
  END A2
  PIN ZN
    DIRECTION OUTPUT ;
    USE SIGNAL ;
    ANTENNADIFFAREA 0.004232 ;
    PORT
      LAYER metal1 ;
        RECT 0.081 0.039 0.111 0.213 ;
    END
  END ZN
  PIN VDD
    DIRECTION INOUT ;
    USE POWER ;
    PORT
      LAYER metal0 ;
        RECT -0.019 0.225 0.211 0.279 ;
    END
  END VDD
  PIN VSS
    DIRECTION INOUT ;
    USE GROUND ;
    PORT
      LAYER metal0 ;
        RECT -0.019 -0.027 0.211 0.027 ;
    END
  END VSS
  OBS
    LAYER metal0 ;
      RECT 0.119 0.117 0.169 0.135 ;
      RECT 0.023 0.081 0.073 0.099 ;
      RECT 0.087 0.189 0.169 0.207 ;
      RECT 0.087 0.045 0.105 0.063 ;
  END
END NOR2_X1

MACRO NOR2_X2
  CLASS CORE ;
  FOREIGN NOR2_X2 0 0 ;
  SIZE 0.32 BY 0.252 ;
  ORIGIN 0.0 0.0 ;
  SYMMETRY X Y ;
  PIN A1
    DIRECTION INPUT ;
    USE SIGNAL ;
    ANTENNAGATEAREA 0.002484 ;
    PORT
      LAYER metal1 ;
        RECT 0.017 0.075 0.047 0.141 ;
    END
  END A1
  PIN A2
    DIRECTION INPUT ;
    USE SIGNAL ;
    ANTENNAGATEAREA 0.003312 ;
    PORT
      LAYER metal1 ;
        RECT 0.081 0.075 0.111 0.177 ;
    END
  END A2
  PIN ZN
    DIRECTION OUTPUT ;
    USE SIGNAL ;
    ANTENNADIFFAREA 0.006348 ;
    PORT
      LAYER metal1 ;
        RECT 0.145 0.039 0.175 0.213 ;
    END
  END ZN
  PIN VDD
    DIRECTION INOUT ;
    USE POWER ;
    PORT
      LAYER metal0 ;
        RECT -0.019 0.225 0.339 0.279 ;
    END
  END VDD
  PIN VSS
    DIRECTION INOUT ;
    USE GROUND ;
    PORT
      LAYER metal0 ;
        RECT -0.019 -0.027 0.339 0.027 ;
    END
  END VSS
  OBS
    LAYER metal0 ;
      RECT 0.119 0.153 0.201 0.171 ;
      RECT 0.023 0.081 0.073 0.099 ;
      RECT 0.023 0.117 0.201 0.135 ;
      RECT 0.055 0.153 0.105 0.171 ;
      RECT 0.087 0.081 0.265 0.099 ;
      RECT 0.151 0.189 0.169 0.207 ;
      RECT 0.087 0.045 0.233 0.063 ;
  END
END NOR2_X2

MACRO NOR2_X4
  CLASS CORE ;
  FOREIGN NOR2_X4 0 0 ;
  SIZE 0.576 BY 0.252 ;
  ORIGIN 0.0 0.0 ;
  SYMMETRY X Y ;
  PIN A1
    DIRECTION INPUT ;
    USE SIGNAL ;
    ANTENNAGATEAREA 0.006624 ;
    PORT
      LAYER metal1 ;
        RECT 0.209 0.111 0.239 0.141 ;
    END
  END A1
  PIN A2
    DIRECTION INPUT ;
    USE SIGNAL ;
    ANTENNAGATEAREA 0.006624 ;
    PORT
      LAYER metal1 ;
        RECT 0.401 0.111 0.431 0.141 ;
    END
  END A2
  PIN ZN
    DIRECTION OUTPUT ;
    USE SIGNAL ;
    ANTENNADIFFAREA 0.014812 ;
    PORT
      LAYER metal1 ;
        RECT 0.337 0.039 0.367 0.177 ;
        RECT 0.465 0.039 0.495 0.177 ;
    END
  END ZN
  PIN VDD
    DIRECTION INOUT ;
    USE POWER ;
    PORT
      LAYER metal0 ;
        RECT -0.019 0.225 0.595 0.279 ;
    END
  END VDD
  PIN VSS
    DIRECTION INOUT ;
    USE GROUND ;
    PORT
      LAYER metal0 ;
        RECT -0.019 -0.027 0.595 0.027 ;
    END
  END VSS
  OBS
    LAYER metal0 ;
      RECT 0.023 0.189 0.553 0.207 ;
      RECT 0.055 0.117 0.265 0.135 ;
      RECT 0.311 0.117 0.521 0.135 ;
      RECT 0.023 0.045 0.553 0.063 ;
      RECT 0.343 0.153 0.361 0.171 ;
      RECT 0.471 0.153 0.489 0.171 ;
  END
END NOR2_X4

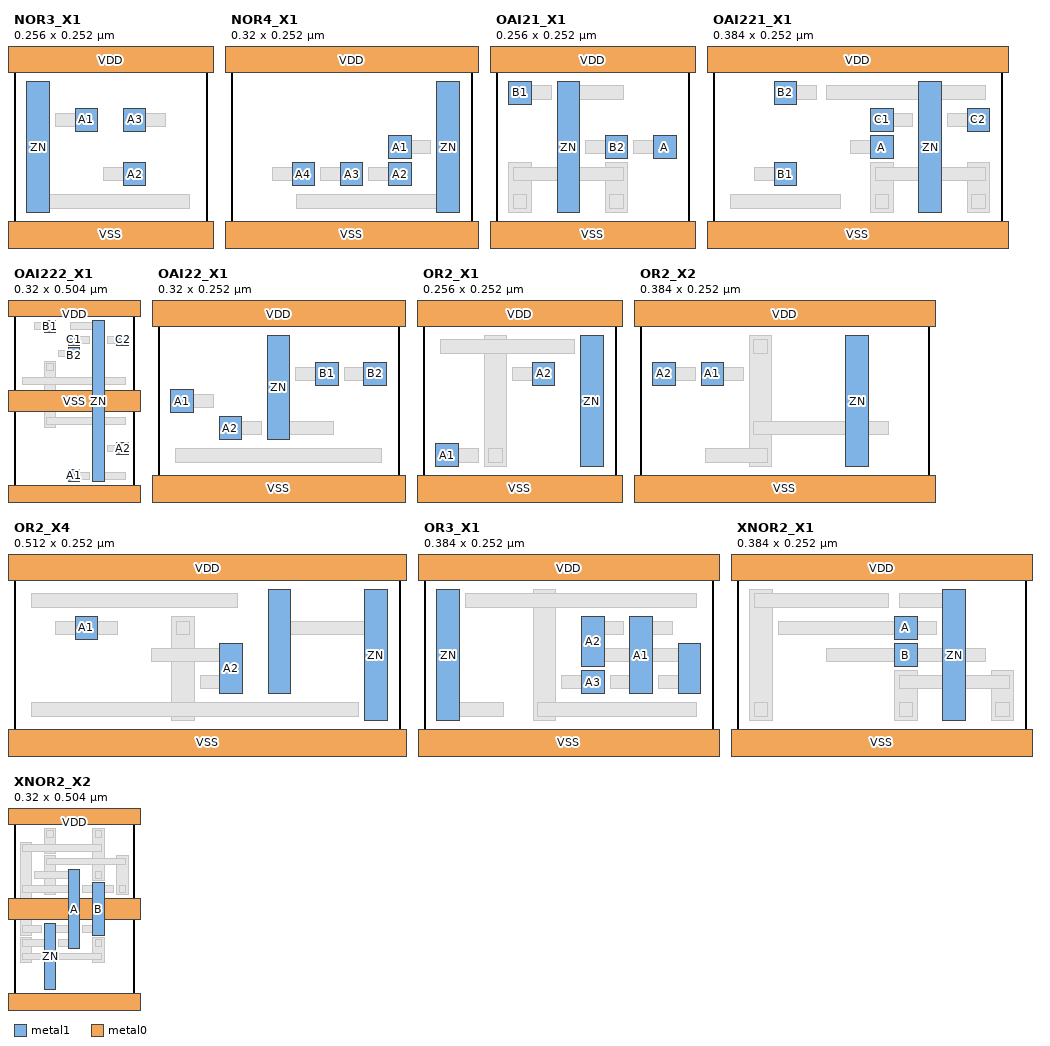
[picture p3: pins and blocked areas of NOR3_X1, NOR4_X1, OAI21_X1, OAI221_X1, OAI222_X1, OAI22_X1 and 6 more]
MACRO NOR3_X1
  CLASS CORE ;
  FOREIGN NOR3_X1 0 0 ;
  SIZE 0.256 BY 0.252 ;
  ORIGIN 0.0 0.0 ;
  SYMMETRY X Y ;
  PIN A1
    DIRECTION INPUT ;
    USE SIGNAL ;
    ANTENNAGATEAREA 0.001656 ;
    PORT
      LAYER metal1 ;
        RECT 0.081 0.147 0.111 0.177 ;
    END
  END A1
  PIN A2
    DIRECTION INPUT ;
    USE SIGNAL ;
    ANTENNAGATEAREA 0.001656 ;
    PORT
      LAYER metal1 ;
        RECT 0.145 0.075 0.175 0.105 ;
    END
  END A2
  PIN A3
    DIRECTION INPUT ;
    USE SIGNAL ;
    ANTENNAGATEAREA 0.001656 ;
    PORT
      LAYER metal1 ;
        RECT 0.145 0.147 0.175 0.177 ;
    END
  END A3
  PIN ZN
    DIRECTION OUTPUT ;
    USE SIGNAL ;
    ANTENNADIFFAREA 0.006348 ;
    PORT
      LAYER metal1 ;
        RECT 0.017 0.039 0.047 0.213 ;
    END
  END ZN
  PIN VDD
    DIRECTION INOUT ;
    USE POWER ;
    PORT
      LAYER metal0 ;
        RECT -0.019 0.225 0.275 0.279 ;
    END
  END VDD
  PIN VSS
    DIRECTION INOUT ;
    USE GROUND ;
    PORT
      LAYER metal0 ;
        RECT -0.019 -0.027 0.275 0.027 ;
    END
  END VSS
  OBS
    LAYER metal0 ;
      RECT 0.055 0.153 0.105 0.171 ;
      RECT 0.119 0.081 0.169 0.099 ;
      RECT 0.151 0.153 0.201 0.171 ;
      RECT 0.023 0.189 0.041 0.207 ;
      RECT 0.023 0.045 0.233 0.063 ;
  END
END NOR3_X1

MACRO NOR4_X1
  CLASS CORE ;
  FOREIGN NOR4_X1 0 0 ;
  SIZE 0.32 BY 0.252 ;
  ORIGIN 0.0 0.0 ;
  SYMMETRY X Y ;
  PIN A1
    DIRECTION INPUT ;
    USE SIGNAL ;
    ANTENNAGATEAREA 0.001656 ;
    PORT
      LAYER metal1 ;
        RECT 0.209 0.111 0.239 0.141 ;
    END
  END A1
  PIN A2
    DIRECTION INPUT ;
    USE SIGNAL ;
    ANTENNAGATEAREA 0.001656 ;
    PORT
      LAYER metal1 ;
        RECT 0.209 0.075 0.239 0.105 ;
    END
  END A2
  PIN A3
    DIRECTION INPUT ;
    USE SIGNAL ;
    ANTENNAGATEAREA 0.001656 ;
    PORT
      LAYER metal1 ;
        RECT 0.145 0.075 0.175 0.105 ;
    END
  END A3
  PIN A4
    DIRECTION INPUT ;
    USE SIGNAL ;
    ANTENNAGATEAREA 0.001656 ;
    PORT
      LAYER metal1 ;
        RECT 0.081 0.075 0.111 0.105 ;
    END
  END A4
  PIN ZN
    DIRECTION OUTPUT ;
    USE SIGNAL ;
    ANTENNADIFFAREA 0.006348 ;
    PORT
      LAYER metal1 ;
        RECT 0.273 0.039 0.303 0.213 ;
    END
  END ZN
  PIN VDD
    DIRECTION INOUT ;
    USE POWER ;
    PORT
      LAYER metal0 ;
        RECT -0.019 0.225 0.339 0.279 ;
    END
  END VDD
  PIN VSS
    DIRECTION INOUT ;
    USE GROUND ;
    PORT
      LAYER metal0 ;
        RECT -0.019 -0.027 0.339 0.027 ;
    END
  END VSS
  OBS
    LAYER metal0 ;
      RECT 0.215 0.117 0.265 0.135 ;
      RECT 0.183 0.081 0.233 0.099 ;
      RECT 0.119 0.081 0.169 0.099 ;
      RECT 0.055 0.081 0.105 0.099 ;
      RECT 0.279 0.189 0.297 0.207 ;
      RECT 0.087 0.045 0.297 0.063 ;
  END
END NOR4_X1

MACRO OAI21_X1
  CLASS CORE ;
  FOREIGN OAI21_X1 0 0 ;
  SIZE 0.256 BY 0.252 ;
  ORIGIN 0.0 0.0 ;
  SYMMETRY X Y ;
  PIN A
    DIRECTION INPUT ;
    USE SIGNAL ;
    ANTENNAGATEAREA 0.001656 ;
    PORT
      LAYER metal1 ;
        RECT 0.209 0.111 0.239 0.141 ;
    END
  END A
  PIN B1
    DIRECTION INPUT ;
    USE SIGNAL ;
    ANTENNAGATEAREA 0.001656 ;
    PORT
      LAYER metal1 ;
        RECT 0.017 0.183 0.047 0.213 ;
    END
  END B1
  PIN B2
    DIRECTION INPUT ;
    USE SIGNAL ;
    ANTENNAGATEAREA 0.001656 ;
    PORT
      LAYER metal1 ;
        RECT 0.145 0.111 0.175 0.141 ;
    END
  END B2
  PIN ZN
    DIRECTION OUTPUT ;
    USE SIGNAL ;
    ANTENNADIFFAREA 0.004232 ;
    PORT
      LAYER metal1 ;
        RECT 0.081 0.039 0.111 0.213 ;
    END
  END ZN
  PIN VDD
    DIRECTION INOUT ;
    USE POWER ;
    PORT
      LAYER metal0 ;
        RECT -0.019 0.225 0.275 0.279 ;
    END
  END VDD
  PIN VSS
    DIRECTION INOUT ;
    USE GROUND ;
    PORT
      LAYER metal0 ;
        RECT -0.019 -0.027 0.275 0.027 ;
    END
  END VSS
  OBS
    LAYER metal1 ;
      RECT 0.017 0.039 0.047 0.105 ;
      RECT 0.145 0.039 0.175 0.105 ;
    LAYER metal0 ;
      RECT 0.023 0.081 0.169 0.099 ;
      RECT 0.023 0.045 0.041 0.063 ;
      RECT 0.151 0.045 0.169 0.063 ;
      RECT 0.183 0.117 0.233 0.135 ;
      RECT 0.023 0.189 0.073 0.207 ;
      RECT 0.119 0.117 0.169 0.135 ;
      RECT 0.087 0.189 0.169 0.207 ;
      RECT 0.087 0.045 0.105 0.063 ;
  END
END OAI21_X1

MACRO OAI221_X1
  CLASS CORE ;
  FOREIGN OAI221_X1 0 0 ;
  SIZE 0.384 BY 0.252 ;
  ORIGIN 0.0 0.0 ;
  SYMMETRY X Y ;
  PIN A
    DIRECTION INPUT ;
    USE SIGNAL ;
    ANTENNAGATEAREA 0.001656 ;
    PORT
      LAYER metal1 ;
        RECT 0.209 0.111 0.239 0.141 ;
    END
  END A
  PIN B1
    DIRECTION INPUT ;
    USE SIGNAL ;
    ANTENNAGATEAREA 0.001656 ;
    PORT
      LAYER metal1 ;
        RECT 0.081 0.075 0.111 0.105 ;
    END
  END B1
  PIN B2
    DIRECTION INPUT ;
    USE SIGNAL ;
    ANTENNAGATEAREA 0.001656 ;
    PORT
      LAYER metal1 ;
        RECT 0.081 0.183 0.111 0.213 ;
    END
  END B2
  PIN C1
    DIRECTION INPUT ;
    USE SIGNAL ;
    ANTENNAGATEAREA 0.001656 ;
    PORT
      LAYER metal1 ;
        RECT 0.209 0.147 0.239 0.177 ;
    END
  END C1
  PIN C2
    DIRECTION INPUT ;
    USE SIGNAL ;
    ANTENNAGATEAREA 0.001656 ;
    PORT
      LAYER metal1 ;
        RECT 0.337 0.147 0.367 0.177 ;
    END
  END C2
  PIN ZN
    DIRECTION OUTPUT ;
    USE SIGNAL ;
    ANTENNADIFFAREA 0.006348 ;
    PORT
      LAYER metal1 ;
        RECT 0.273 0.039 0.303 0.213 ;
    END
  END ZN
  PIN VDD
    DIRECTION INOUT ;
    USE POWER ;
    PORT
      LAYER metal0 ;
        RECT -0.019 0.225 0.403 0.279 ;
    END
  END VDD
  PIN VSS
    DIRECTION INOUT ;
    USE GROUND ;
    PORT
      LAYER metal0 ;
        RECT -0.019 -0.027 0.403 0.027 ;
    END
  END VSS
  OBS
    LAYER metal1 ;
      RECT 0.209 0.039 0.239 0.105 ;
      RECT 0.337 0.039 0.367 0.105 ;
    LAYER metal0 ;
      RECT 0.023 0.045 0.169 0.063 ;
      RECT 0.215 0.081 0.361 0.099 ;
      RECT 0.215 0.045 0.233 0.063 ;
      RECT 0.343 0.045 0.361 0.063 ;
      RECT 0.183 0.117 0.233 0.135 ;
      RECT 0.055 0.081 0.105 0.099 ;
      RECT 0.087 0.189 0.137 0.207 ;
      RECT 0.215 0.153 0.265 0.171 ;
      RECT 0.311 0.153 0.361 0.171 ;
      RECT 0.279 0.045 0.297 0.063 ;
      RECT 0.151 0.189 0.361 0.207 ;
  END
END OAI221_X1

MACRO OAI222_X1
  CLASS CORE ;
  FOREIGN OAI222_X1 0 0 ;
  SIZE 0.32 BY 0.504 ;
  ORIGIN 0.0 0.0 ;
  SYMMETRY X Y ;
  PIN A1
    DIRECTION INPUT ;
    USE SIGNAL ;
    ANTENNAGATEAREA 0.001656 ;
    PORT
      LAYER metal1 ;
        RECT 0.145 0.039 0.175 0.069 ;
    END
  END A1
  PIN A2
    DIRECTION INPUT ;
    USE SIGNAL ;
    ANTENNAGATEAREA 0.001656 ;
    PORT
      LAYER metal1 ;
        RECT 0.273 0.111 0.303 0.141 ;
    END
  END A2
  PIN B1
    DIRECTION INPUT ;
    USE SIGNAL ;
    ANTENNAGATEAREA 0.001656 ;
    PORT
      LAYER metal1 ;
        RECT 0.081 0.435 0.111 0.465 ;
    END
  END B1
  PIN B2
    DIRECTION INPUT ;
    USE SIGNAL ;
    ANTENNAGATEAREA 0.001656 ;
    PORT
      LAYER metal1 ;
        RECT 0.145 0.363 0.175 0.393 ;
    END
  END B2
  PIN C1
    DIRECTION INPUT ;
    USE SIGNAL ;
    ANTENNAGATEAREA 0.001656 ;
    PORT
      LAYER metal1 ;
        RECT 0.145 0.399 0.175 0.429 ;
    END
  END C1
  PIN C2
    DIRECTION INPUT ;
    USE SIGNAL ;
    ANTENNAGATEAREA 0.001656 ;
    PORT
      LAYER metal1 ;
        RECT 0.273 0.399 0.303 0.429 ;
    END
  END C2
  PIN ZN
    DIRECTION OUTPUT ;
    USE SIGNAL ;
    ANTENNADIFFAREA 0.006348 ;
    PORT
      LAYER metal1 ;
        RECT 0.209 0.039 0.239 0.465 ;
    END
  END ZN
  PIN VDD
    DIRECTION INOUT ;
    USE POWER ;
    PORT
      LAYER metal0 ;
        RECT -0.019 -0.027 0.339 0.027 ;
        RECT -0.019 0.477 0.339 0.531 ;
    END
  END VDD
  PIN VSS
    DIRECTION INOUT ;
    USE GROUND ;
    PORT
      LAYER metal0 ;
        RECT -0.019 0.225 0.339 0.279 ;
    END
  END VSS
  OBS
    LAYER metal1 ;
      RECT 0.081 0.183 0.111 0.357 ;
    LAYER metal0 ;
      RECT 0.087 0.333 0.105 0.351 ;
      RECT 0.087 0.189 0.297 0.207 ;
      RECT 0.023 0.297 0.297 0.315 ;
      RECT 0.151 0.045 0.201 0.063 ;
      RECT 0.247 0.117 0.297 0.135 ;
      RECT 0.055 0.441 0.105 0.459 ;
      RECT 0.119 0.369 0.169 0.387 ;
      RECT 0.151 0.405 0.201 0.423 ;
      RECT 0.247 0.405 0.297 0.423 ;
      RECT 0.215 0.153 0.233 0.171 ;
      RECT 0.151 0.441 0.233 0.459 ;
      RECT 0.215 0.045 0.297 0.063 ;
  END
END OAI222_X1

MACRO OAI22_X1
  CLASS CORE ;
  FOREIGN OAI22_X1 0 0 ;
  SIZE 0.32 BY 0.252 ;
  ORIGIN 0.0 0.0 ;
  SYMMETRY X Y ;
  PIN A1
    DIRECTION INPUT ;
    USE SIGNAL ;
    ANTENNAGATEAREA 0.001656 ;
    PORT
      LAYER metal1 ;
        RECT 0.017 0.111 0.047 0.141 ;
    END
  END A1
  PIN A2
    DIRECTION INPUT ;
    USE SIGNAL ;
    ANTENNAGATEAREA 0.001656 ;
    PORT
      LAYER metal1 ;
        RECT 0.081 0.075 0.111 0.105 ;
    END
  END A2
  PIN B1
    DIRECTION INPUT ;
    USE SIGNAL ;
    ANTENNAGATEAREA 0.001656 ;
    PORT
      LAYER metal1 ;
        RECT 0.209 0.147 0.239 0.177 ;
    END
  END B1
  PIN B2
    DIRECTION INPUT ;
    USE SIGNAL ;
    ANTENNAGATEAREA 0.001656 ;
    PORT
      LAYER metal1 ;
        RECT 0.273 0.147 0.303 0.177 ;
    END
  END B2
  PIN ZN
    DIRECTION OUTPUT ;
    USE SIGNAL ;
    ANTENNADIFFAREA 0.004232 ;
    PORT
      LAYER metal1 ;
        RECT 0.145 0.075 0.175 0.213 ;
    END
  END ZN
  PIN VDD
    DIRECTION INOUT ;
    USE POWER ;
    PORT
      LAYER metal0 ;
        RECT -0.019 0.225 0.339 0.279 ;
    END
  END VDD
  PIN VSS
    DIRECTION INOUT ;
    USE GROUND ;
    PORT
      LAYER metal0 ;
        RECT -0.019 -0.027 0.339 0.027 ;
    END
  END VSS
  OBS
    LAYER metal0 ;
      RECT 0.023 0.045 0.297 0.063 ;
      RECT 0.023 0.117 0.073 0.135 ;
      RECT 0.087 0.081 0.137 0.099 ;
      RECT 0.183 0.153 0.233 0.171 ;
      RECT 0.247 0.153 0.297 0.171 ;
      RECT 0.151 0.081 0.233 0.099 ;
      RECT 0.151 0.189 0.169 0.207 ;
  END
END OAI22_X1

MACRO OR2_X1
  CLASS CORE ;
  FOREIGN OR2_X1 0 0 ;
  SIZE 0.256 BY 0.252 ;
  ORIGIN 0.0 0.0 ;
  SYMMETRY X Y ;
  PIN A1
    DIRECTION INPUT ;
    USE SIGNAL ;
    ANTENNAGATEAREA 0.001656 ;
    PORT
      LAYER metal1 ;
        RECT 0.017 0.039 0.047 0.069 ;
    END
  END A1
  PIN A2
    DIRECTION INPUT ;
    USE SIGNAL ;
    ANTENNAGATEAREA 0.001656 ;
    PORT
      LAYER metal1 ;
        RECT 0.145 0.147 0.175 0.177 ;
    END
  END A2
  PIN ZN
    DIRECTION OUTPUT ;
    USE SIGNAL ;
    ANTENNADIFFAREA 0.004232 ;
    PORT
      LAYER metal1 ;
        RECT 0.209 0.039 0.239 0.213 ;
    END
  END ZN
  PIN VDD
    DIRECTION INOUT ;
    USE POWER ;
    PORT
      LAYER metal0 ;
        RECT -0.019 0.225 0.275 0.279 ;
    END
  END VDD
  PIN VSS
    DIRECTION INOUT ;
    USE GROUND ;
    PORT
      LAYER metal0 ;
        RECT -0.019 -0.027 0.275 0.027 ;
    END
  END VSS
  OBS
    LAYER metal1 ;
      RECT 0.081 0.039 0.111 0.213 ;
    LAYER metal0 ;
      RECT 0.023 0.189 0.201 0.207 ;
      RECT 0.087 0.045 0.105 0.063 ;
      RECT 0.023 0.045 0.073 0.063 ;
      RECT 0.119 0.153 0.169 0.171 ;
      RECT 0.215 0.045 0.233 0.063 ;
      RECT 0.215 0.189 0.233 0.207 ;
  END
END OR2_X1

MACRO OR2_X2
  CLASS CORE ;
  FOREIGN OR2_X2 0 0 ;
  SIZE 0.384 BY 0.252 ;
  ORIGIN 0.0 0.0 ;
  SYMMETRY X Y ;
  PIN A1
    DIRECTION INPUT ;
    USE SIGNAL ;
    ANTENNAGATEAREA 0.001656 ;
    PORT
      LAYER metal1 ;
        RECT 0.081 0.147 0.111 0.177 ;
    END
  END A1
  PIN A2
    DIRECTION INPUT ;
    USE SIGNAL ;
    ANTENNAGATEAREA 0.001656 ;
    PORT
      LAYER metal1 ;
        RECT 0.017 0.147 0.047 0.177 ;
    END
  END A2
  PIN ZN
    DIRECTION OUTPUT ;
    USE SIGNAL ;
    ANTENNADIFFAREA 0.004232 ;
    PORT
      LAYER metal1 ;
        RECT 0.273 0.039 0.303 0.213 ;
    END
  END ZN
  PIN VDD
    DIRECTION INOUT ;
    USE POWER ;
    PORT
      LAYER metal0 ;
        RECT -0.019 0.225 0.403 0.279 ;
    END
  END VDD
  PIN VSS
    DIRECTION INOUT ;
    USE GROUND ;
    PORT
      LAYER metal0 ;
        RECT -0.019 -0.027 0.403 0.027 ;
    END
  END VSS
  OBS
    LAYER metal1 ;
      RECT 0.145 0.039 0.175 0.213 ;
    LAYER metal0 ;
      RECT 0.151 0.081 0.329 0.099 ;
      RECT 0.087 0.045 0.169 0.063 ;
      RECT 0.151 0.189 0.169 0.207 ;
      RECT 0.087 0.153 0.137 0.171 ;
      RECT 0.023 0.153 0.073 0.171 ;
      RECT 0.279 0.045 0.297 0.063 ;
      RECT 0.279 0.189 0.297 0.207 ;
  END
END OR2_X2

MACRO OR2_X4
  CLASS CORE ;
  FOREIGN OR2_X4 0 0 ;
  SIZE 0.512 BY 0.252 ;
  ORIGIN 0.0 0.0 ;
  SYMMETRY X Y ;
  PIN A1
    DIRECTION INPUT ;
    USE SIGNAL ;
    ANTENNAGATEAREA 0.003312 ;
    PORT
      LAYER metal1 ;
        RECT 0.081 0.147 0.111 0.177 ;
    END
  END A1
  PIN A2
    DIRECTION INPUT ;
    USE SIGNAL ;
    ANTENNAGATEAREA 0.003312 ;
    PORT
      LAYER metal1 ;
        RECT 0.273 0.075 0.303 0.141 ;
    END
  END A2
  PIN ZN
    DIRECTION OUTPUT ;
    USE SIGNAL ;
    ANTENNADIFFAREA 0.008464 ;
    PORT
      LAYER metal1 ;
        RECT 0.337 0.075 0.367 0.213 ;
        RECT 0.465 0.039 0.495 0.213 ;
    END
  END ZN
  PIN VDD
    DIRECTION INOUT ;
    USE POWER ;
    PORT
      LAYER metal0 ;
        RECT -0.019 0.225 0.531 0.279 ;
    END
  END VDD
  PIN VSS
    DIRECTION INOUT ;
    USE GROUND ;
    PORT
      LAYER metal0 ;
        RECT -0.019 -0.027 0.531 0.027 ;
    END
  END VSS
  OBS
    LAYER metal1 ;
      RECT 0.209 0.039 0.239 0.177 ;
    LAYER metal0 ;
      RECT 0.023 0.189 0.297 0.207 ;
      RECT 0.023 0.045 0.457 0.063 ;
      RECT 0.215 0.153 0.233 0.171 ;
      RECT 0.055 0.153 0.137 0.171 ;
      RECT 0.183 0.117 0.297 0.135 ;
      RECT 0.247 0.081 0.297 0.099 ;
      RECT 0.343 0.081 0.361 0.099 ;
      RECT 0.343 0.189 0.361 0.207 ;
      RECT 0.343 0.153 0.489 0.171 ;
      RECT 0.471 0.045 0.489 0.063 ;
      RECT 0.471 0.189 0.489 0.207 ;
  END
END OR2_X4

MACRO OR3_X1
  CLASS CORE ;
  FOREIGN OR3_X1 0 0 ;
  SIZE 0.384 BY 0.252 ;
  ORIGIN 0.0 0.0 ;
  SYMMETRY X Y ;
  PIN A1
    DIRECTION INPUT ;
    USE SIGNAL ;
    ANTENNAGATEAREA 0.001656 ;
    PORT
      LAYER metal1 ;
        RECT 0.273 0.075 0.303 0.177 ;
    END
  END A1
  PIN A2
    DIRECTION INPUT ;
    USE SIGNAL ;
    ANTENNAGATEAREA 0.001656 ;
    PORT
      LAYER metal1 ;
        RECT 0.209 0.111 0.239 0.177 ;
        RECT 0.337 0.075 0.367 0.141 ;
    END
  END A2
  PIN A3
    DIRECTION INPUT ;
    USE SIGNAL ;
    ANTENNAGATEAREA 0.001656 ;
    PORT
      LAYER metal1 ;
        RECT 0.209 0.075 0.239 0.105 ;
    END
  END A3
  PIN ZN
    DIRECTION OUTPUT ;
    USE SIGNAL ;
    ANTENNADIFFAREA 0.004232 ;
    PORT
      LAYER metal1 ;
        RECT 0.017 0.039 0.047 0.213 ;
    END
  END ZN
  PIN VDD
    DIRECTION INOUT ;
    USE POWER ;
    PORT
      LAYER metal0 ;
        RECT -0.019 0.225 0.403 0.279 ;
    END
  END VDD
  PIN VSS
    DIRECTION INOUT ;
    USE GROUND ;
    PORT
      LAYER metal0 ;
        RECT -0.019 -0.027 0.403 0.027 ;
    END
  END VSS
  OBS
    LAYER metal1 ;
      RECT 0.145 0.039 0.175 0.213 ;
    LAYER metal0 ;
      RECT 0.055 0.189 0.361 0.207 ;
      RECT 0.151 0.045 0.361 0.063 ;
      RECT 0.279 0.153 0.329 0.171 ;
      RECT 0.247 0.081 0.297 0.099 ;
      RECT 0.215 0.117 0.361 0.135 ;
      RECT 0.215 0.153 0.265 0.171 ;
      RECT 0.311 0.081 0.361 0.099 ;
      RECT 0.183 0.081 0.233 0.099 ;
      RECT 0.023 0.189 0.041 0.207 ;
      RECT 0.023 0.045 0.105 0.063 ;
  END
END OR3_X1

MACRO XNOR2_X1
  CLASS CORE ;
  FOREIGN XNOR2_X1 0 0 ;
  SIZE 0.384 BY 0.252 ;
  ORIGIN 0.0 0.0 ;
  SYMMETRY X Y ;
  PIN A
    DIRECTION INPUT ;
    USE SIGNAL ;
    ANTENNAGATEAREA 0.003312 ;
    PORT
      LAYER metal1 ;
        RECT 0.209 0.147 0.239 0.177 ;
    END
  END A
  PIN B
    DIRECTION INPUT ;
    USE SIGNAL ;
    ANTENNAGATEAREA 0.003312 ;
    PORT
      LAYER metal1 ;
        RECT 0.209 0.111 0.239 0.141 ;
    END
  END B
  PIN ZN
    DIRECTION OUTPUT ;
    USE SIGNAL ;
    ANTENNADIFFAREA 0.004232 ;
    PORT
      LAYER metal1 ;
        RECT 0.273 0.039 0.303 0.213 ;
    END
  END ZN
  PIN VDD
    DIRECTION INOUT ;
    USE POWER ;
    PORT
      LAYER metal0 ;
        RECT -0.019 0.225 0.403 0.279 ;
    END
  END VDD
  PIN VSS
    DIRECTION INOUT ;
    USE GROUND ;
    PORT
      LAYER metal0 ;
        RECT -0.019 -0.027 0.403 0.027 ;
    END
  END VSS
  OBS
    LAYER metal1 ;
      RECT 0.017 0.039 0.047 0.213 ;
      RECT 0.209 0.039 0.239 0.105 ;
      RECT 0.337 0.039 0.367 0.105 ;
    LAYER metal0 ;
      RECT 0.023 0.189 0.201 0.207 ;
      RECT 0.215 0.081 0.361 0.099 ;
      RECT 0.023 0.045 0.041 0.063 ;
      RECT 0.215 0.045 0.233 0.063 ;
      RECT 0.343 0.045 0.361 0.063 ;
      RECT 0.055 0.153 0.265 0.171 ;
      RECT 0.119 0.117 0.329 0.135 ;
      RECT 0.279 0.045 0.297 0.063 ;
      RECT 0.215 0.189 0.297 0.207 ;
  END
END XNOR2_X1

MACRO XNOR2_X2
  CLASS CORE ;
  FOREIGN XNOR2_X2 0 0 ;
  SIZE 0.32 BY 0.504 ;
  ORIGIN 0.0 0.0 ;
  SYMMETRY X Y ;
  PIN A
    DIRECTION INPUT ;
    USE SIGNAL ;
    ANTENNAGATEAREA 0.004968 ;
    PORT
      LAYER metal1 ;
        RECT 0.145 0.147 0.175 0.357 ;
    END
  END A
  PIN B
    DIRECTION INPUT ;
    USE SIGNAL ;
    ANTENNAGATEAREA 0.004968 ;
    PORT
      LAYER metal1 ;
        RECT 0.209 0.183 0.239 0.321 ;
    END
  END B
  PIN ZN
    DIRECTION OUTPUT ;
    USE SIGNAL ;
    ANTENNADIFFAREA 0.004232 ;
    PORT
      LAYER metal1 ;
        RECT 0.081 0.039 0.111 0.213 ;
    END
  END ZN
  PIN VDD
    DIRECTION INOUT ;
    USE POWER ;
    PORT
      LAYER metal0 ;
        RECT -0.019 0.477 0.339 0.531 ;
        RECT -0.019 -0.027 0.339 0.027 ;
    END
  END VDD
  PIN VSS
    DIRECTION INOUT ;
    USE GROUND ;
    PORT
      LAYER metal0 ;
        RECT -0.019 0.225 0.339 0.279 ;
    END
  END VSS
  OBS
    LAYER metal1 ;
      RECT 0.081 0.291 0.111 0.393 ;
      RECT 0.273 0.291 0.303 0.393 ;
      RECT 0.017 0.183 0.047 0.429 ;
      RECT 0.081 0.399 0.111 0.465 ;
      RECT 0.209 0.327 0.239 0.465 ;
      RECT 0.017 0.111 0.047 0.177 ;
      RECT 0.209 0.111 0.239 0.177 ;
    LAYER metal0 ;
      RECT 0.087 0.369 0.297 0.387 ;
      RECT 0.023 0.297 0.169 0.315 ;
      RECT 0.023 0.405 0.233 0.423 ;
      RECT 0.023 0.189 0.073 0.207 ;
      RECT 0.023 0.153 0.105 0.171 ;
      RECT 0.023 0.117 0.233 0.135 ;
      RECT 0.279 0.297 0.297 0.315 ;
      RECT 0.087 0.441 0.105 0.459 ;
      RECT 0.215 0.441 0.233 0.459 ;
      RECT 0.215 0.333 0.233 0.351 ;
      RECT 0.215 0.153 0.233 0.171 ;
      RECT 0.119 0.153 0.169 0.171 ;
      RECT 0.055 0.333 0.169 0.351 ;
      RECT 0.183 0.189 0.233 0.207 ;
      RECT 0.183 0.297 0.265 0.315 ;
      RECT 0.087 0.189 0.169 0.207 ;
      RECT 0.087 0.045 0.105 0.063 ;
  END
END XNOR2_X2

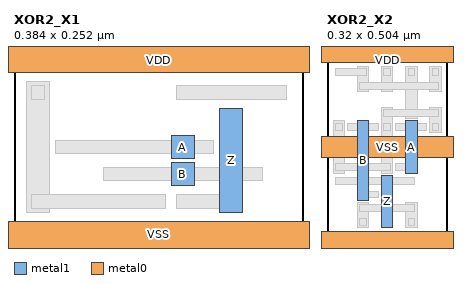
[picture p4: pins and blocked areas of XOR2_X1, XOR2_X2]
MACRO XOR2_X1
  CLASS CORE ;
  FOREIGN XOR2_X1 0 0 ;
  SIZE 0.384 BY 0.252 ;
  ORIGIN 0.0 0.0 ;
  SYMMETRY X Y ;
  PIN A
    DIRECTION INPUT ;
    USE SIGNAL ;
    ANTENNAGATEAREA 0.003312 ;
    PORT
      LAYER metal1 ;
        RECT 0.209 0.111 0.239 0.141 ;
    END
  END A
  PIN B
    DIRECTION INPUT ;
    USE SIGNAL ;
    ANTENNAGATEAREA 0.003312 ;
    PORT
      LAYER metal1 ;
        RECT 0.209 0.075 0.239 0.105 ;
    END
  END B
  PIN Z
    DIRECTION OUTPUT ;
    USE SIGNAL ;
    ANTENNADIFFAREA 0.004232 ;
    PORT
      LAYER metal1 ;
        RECT 0.273 0.039 0.303 0.177 ;
    END
  END Z
  PIN VDD
    DIRECTION INOUT ;
    USE POWER ;
    PORT
      LAYER metal0 ;
        RECT -0.019 0.225 0.403 0.279 ;
    END
  END VDD
  PIN VSS
    DIRECTION INOUT ;
    USE GROUND ;
    PORT
      LAYER metal0 ;
        RECT -0.019 -0.027 0.403 0.027 ;
    END
  END VSS
  OBS
    LAYER metal1 ;
      RECT 0.017 0.039 0.047 0.213 ;
    LAYER metal0 ;
      RECT 0.023 0.045 0.201 0.063 ;
      RECT 0.215 0.189 0.361 0.207 ;
      RECT 0.023 0.189 0.041 0.207 ;
      RECT 0.055 0.117 0.265 0.135 ;
      RECT 0.119 0.081 0.329 0.099 ;
      RECT 0.215 0.045 0.297 0.063 ;
      RECT 0.279 0.153 0.297 0.171 ;
  END
END XOR2_X1

MACRO XOR2_X2
  CLASS CORE ;
  FOREIGN XOR2_X2 0 0 ;
  SIZE 0.32 BY 0.504 ;
  ORIGIN 0.0 0.0 ;
  SYMMETRY X Y ;
  PIN A
    DIRECTION INPUT ;
    USE SIGNAL ;
    ANTENNAGATEAREA 0.004968 ;
    PORT
      LAYER metal1 ;
        RECT 0.209 0.183 0.239 0.321 ;
    END
  END A
  PIN B
    DIRECTION INPUT ;
    USE SIGNAL ;
    ANTENNAGATEAREA 0.004968 ;
    PORT
      LAYER metal1 ;
        RECT 0.081 0.111 0.111 0.321 ;
    END
  END B
  PIN Z
    DIRECTION OUTPUT ;
    USE SIGNAL ;
    ANTENNADIFFAREA 0.006348 ;
    PORT
      LAYER metal1 ;
        RECT 0.145 0.039 0.175 0.177 ;
    END
  END Z
  PIN VDD
    DIRECTION INOUT ;
    USE POWER ;
    PORT
      LAYER metal0 ;
        RECT -0.019 0.477 0.339 0.531 ;
        RECT -0.019 -0.027 0.339 0.027 ;
    END
  END VDD
  PIN VSS
    DIRECTION INOUT ;
    USE GROUND ;
    PORT
      LAYER metal0 ;
        RECT -0.019 0.225 0.339 0.279 ;
    END
  END VSS
  OBS
    LAYER metal1 ;
      RECT 0.017 0.183 0.047 0.321 ;
      RECT 0.145 0.183 0.175 0.357 ;
      RECT 0.209 0.327 0.239 0.465 ;
      RECT 0.273 0.291 0.303 0.357 ;
      RECT 0.081 0.399 0.111 0.465 ;
      RECT 0.145 0.399 0.175 0.465 ;
      RECT 0.273 0.399 0.303 0.465 ;
      RECT 0.081 0.039 0.111 0.105 ;
      RECT 0.209 0.039 0.239 0.105 ;
    LAYER metal0 ;
      RECT 0.151 0.333 0.297 0.351 ;
      RECT 0.023 0.189 0.169 0.207 ;
      RECT 0.023 0.441 0.105 0.459 ;
      RECT 0.087 0.405 0.297 0.423 ;
      RECT 0.087 0.081 0.233 0.099 ;
      RECT 0.215 0.441 0.233 0.459 ;
      RECT 0.023 0.297 0.041 0.315 ;
      RECT 0.151 0.297 0.169 0.315 ;
      RECT 0.279 0.297 0.297 0.315 ;
      RECT 0.151 0.441 0.169 0.459 ;
      RECT 0.279 0.441 0.297 0.459 ;
      RECT 0.087 0.045 0.105 0.063 ;
      RECT 0.215 0.045 0.233 0.063 ;
      RECT 0.183 0.189 0.233 0.207 ;
      RECT 0.183 0.297 0.265 0.315 ;
      RECT 0.055 0.297 0.137 0.315 ;
      RECT 0.087 0.117 0.137 0.135 ;
      RECT 0.023 0.153 0.233 0.171 ;
      RECT 0.151 0.045 0.169 0.063 ;
  END
END XOR2_X2

END LIBRARY
